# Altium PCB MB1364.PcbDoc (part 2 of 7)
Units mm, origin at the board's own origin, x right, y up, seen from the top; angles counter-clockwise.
Board outline 70 x 133.34 mm, 6 copper layers (Top Layer, Signal Layer 1, Signal Layer 2, Signal Layer 3, Signal Layer 4, Bottom Layer), stack 1.57 mm thick; 320 components, 286 nets, 1370 pads, 2009 vias.

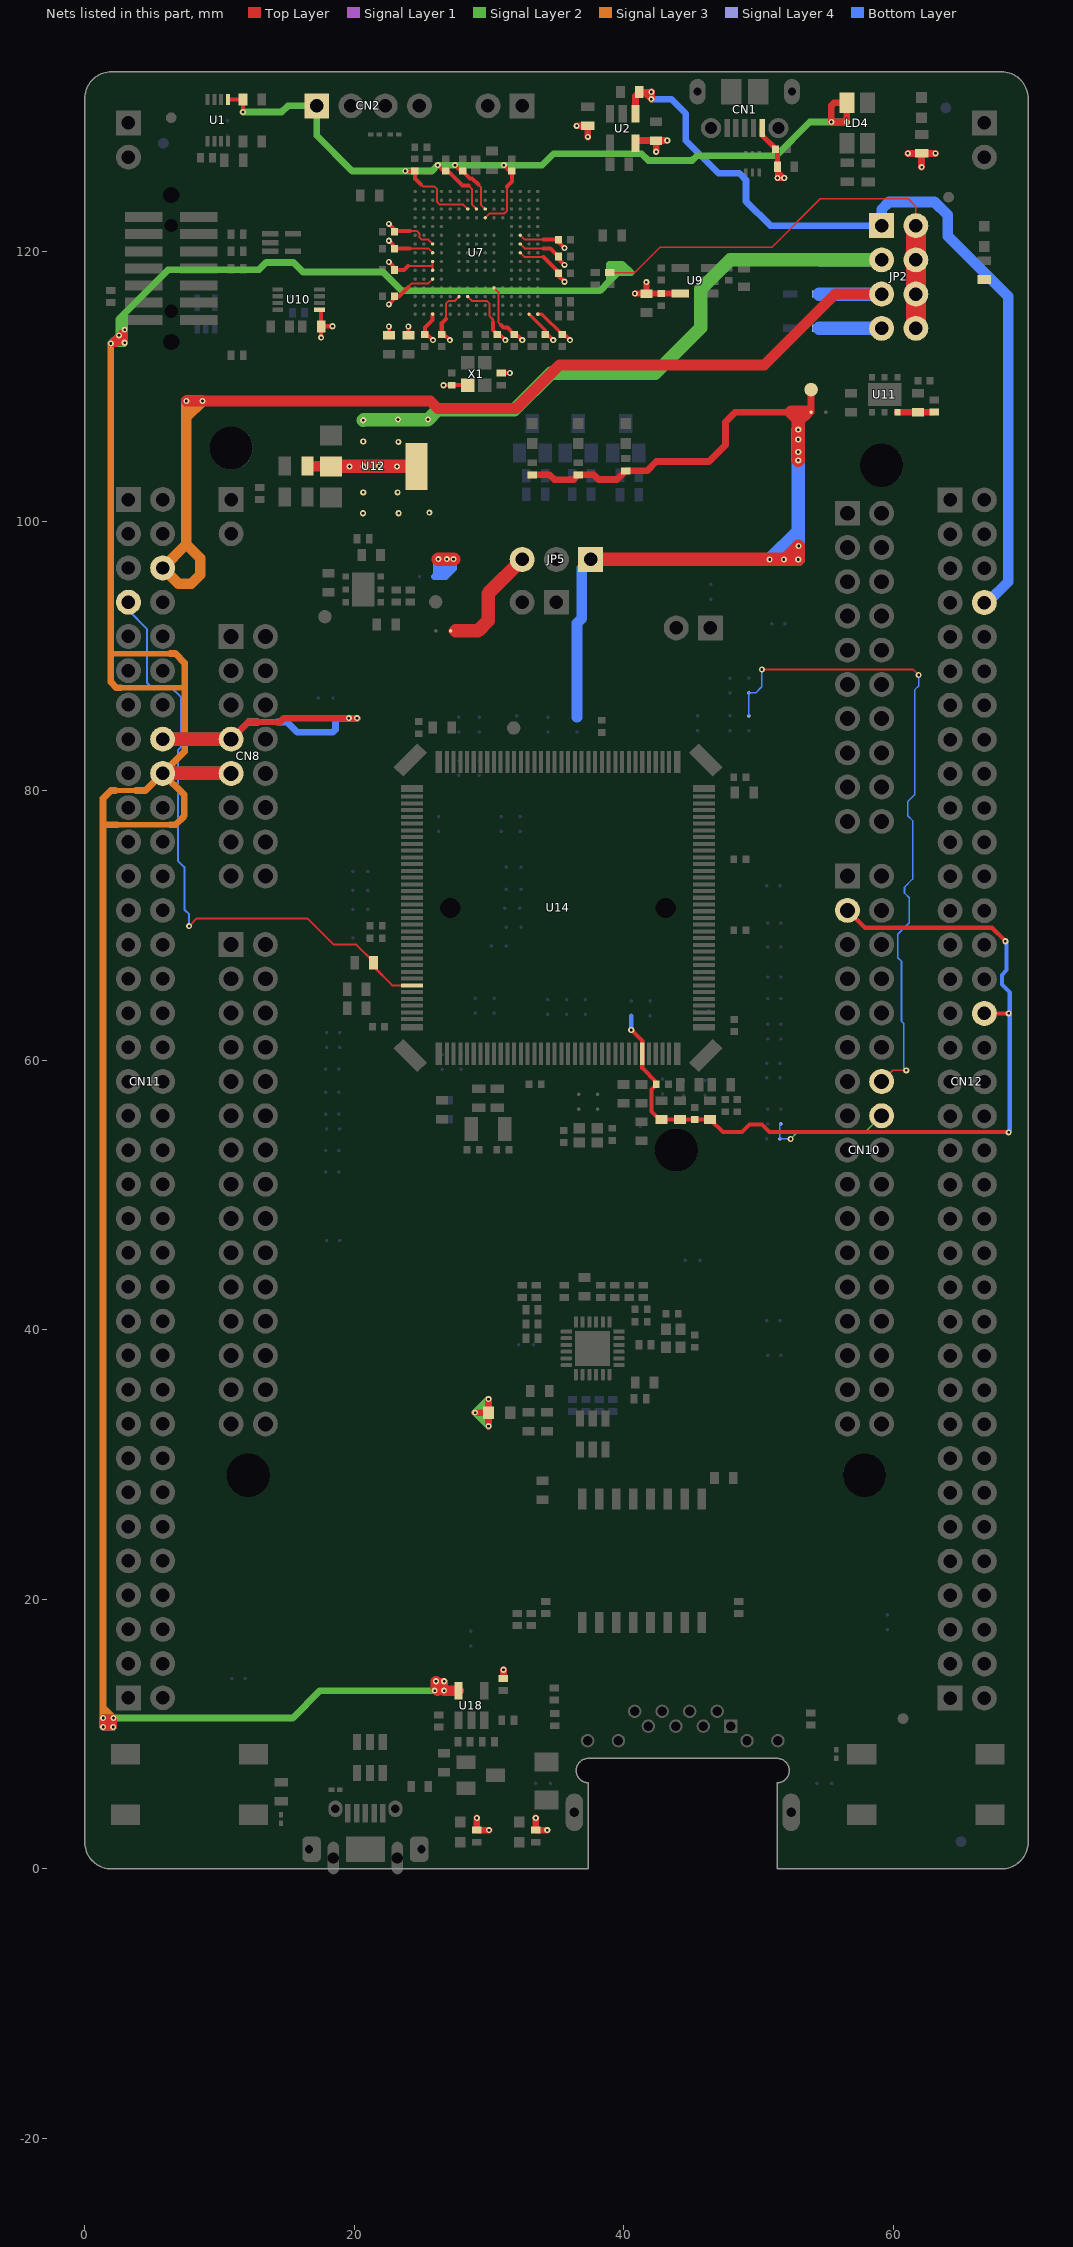
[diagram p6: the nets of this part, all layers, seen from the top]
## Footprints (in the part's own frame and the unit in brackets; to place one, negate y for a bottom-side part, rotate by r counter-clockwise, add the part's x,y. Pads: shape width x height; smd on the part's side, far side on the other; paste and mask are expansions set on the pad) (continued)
ICC_UFBGA201_176+25_10X10_P065 [mm] "IPC"
  round 0.25 smd mask+0.05: A1(-4.55,4.55) A2(-3.9,4.55) A3(-3.25,4.55) A4(-2.6,4.55) A5(-1.95,4.55) A6(-1.3,4.55) A7(-0.65,4.55) A8(0,4.55) A9(0.65,4.55) A10(1.3,4.55) A11(1.95,4.55) A12(2.6,4.55) A13(3.25,4.55) A14(3.9,4.55) A15(4.55,4.55) B1(-4.55,3.9) B2(-3.9,3.9) B3(-3.25,3.9) B4(-2.6,3.9) B5(-1.95,3.9) B6(-1.3,3.9) B7(-0.65,3.9) B8(0,3.9) B9(0.65,3.9) B10(1.3,3.9) B11(1.95,3.9) B12(2.6,3.9) B13(3.25,3.9) B14(3.9,3.9) B15(4.55,3.9) C1(-4.55,3.25) C2(-3.9,3.25) C3(-3.25,3.25) C4(-2.6,3.25) C5(-1.95,3.25) C6(-1.3,3.25) C7(-0.65,3.25) C8(0,3.25) C9(0.65,3.25) C10(1.3,3.25) C11(1.95,3.25) C12(2.6,3.25) C13(3.25,3.25) C14(3.9,3.25) C15(4.55,3.25) D1(-4.55,2.6) D2(-3.9,2.6) D3(-3.25,2.6) D4(-2.6,2.6) D5(-1.95,2.6) D6(-1.3,2.6) D7(-0.65,2.6) D8(0,2.6) D9(0.65,2.6) D10(1.3,2.6) D11(1.95,2.6) D12(2.6,2.6) D13(3.25,2.6) D14(3.9,2.6) D15(4.55,2.6) E1(-4.55,1.95) E2(-3.9,1.95) E3(-3.25,1.95) E4(-2.6,1.95) E12(2.6,1.95) E13(3.25,1.95) E14(3.9,1.95) E15(4.55,1.95) F1(-4.55,1.3) F2(-3.9,1.3) F3(-3.25,1.3) F4(-2.6,1.3) F6(-1.3,1.3) F7(-0.65,1.3) F8(0,1.3) F9(0.65,1.3) F10(1.3,1.3) F12(2.6,1.3) F13(3.25,1.3) F14(3.9,1.3) F15(4.55,1.3) G1(-4.55,0.65) G2(-3.9,0.65) G3(-3.25,0.65) G4(-2.6,0.65) G6(-1.3,0.65) G7(-0.65,0.65) G8(0,0.65) G9(0.65,0.65) G10(1.3,0.65) G12(2.6,0.65) G13(3.25,0.65) G14(3.9,0.65) G15(4.55,0.65) H1(-4.55,0) H2(-3.9,0) H3(-3.25,0) H4(-2.6,0) H6(-1.3,0) H7(-0.65,0) H8(0,0) H9(0.65,0) H10(1.3,0) H12(2.6,0) H13(3.25,0) H14(3.9,0) H15(4.55,0) J1(-4.55,-0.65) J2(-3.9,-0.65) J3(-3.25,-0.65) J4(-2.6,-0.65) J6(-1.3,-0.65) J7(-0.65,-0.65) J8(0,-0.65) J9(0.65,-0.65) J10(1.3,-0.65) J12(2.6,-0.65) J13(3.25,-0.65) J14(3.9,-0.65) J15(4.55,-0.65) K1(-4.55,-1.3) K2(-3.9,-1.3) K3(-3.25,-1.3) K4(-2.6,-1.3) K6(-1.3,-1.3) K7(-0.65,-1.3) K8(0,-1.3) K9(0.65,-1.3) K10(1.3,-1.3) K12(2.6,-1.3) K13(3.25,-1.3) K14(3.9,-1.3) K15(4.55,-1.3) L1(-4.55,-1.95) L2(-3.9,-1.95) L3(-3.25,-1.95) L4(-2.6,-1.95) L12(2.6,-1.95) L13(3.25,-1.95) L14(3.9,-1.95) L15(4.55,-1.95) M1(-4.55,-2.6) M2(-3.9,-2.6) M3(-3.25,-2.6) M4(-2.6,-2.6) M5(-1.95,-2.6) M6(-1.3,-2.6) M7(-0.65,-2.6) M8(0,-2.6) M9(0.65,-2.6) M10(1.3,-2.6) M11(1.95,-2.6) M12(2.6,-2.6) M13(3.25,-2.6) M14(3.9,-2.6) M15(4.55,-2.6) N1(-4.55,-3.25) N2(-3.9,-3.25) N3(-3.25,-3.25) N4(-2.6,-3.25) N5(-1.95,-3.25) N6(-1.3,-3.25) N7(-0.65,-3.25) N8(0,-3.25) N9(0.65,-3.25) N10(1.3,-3.25) N11(1.95,-3.25) N12(2.6,-3.25) N13(3.25,-3.25) N14(3.9,-3.25) N15(4.55,-3.25) P1(-4.55,-3.9) P2(-3.9,-3.9) P3(-3.25,-3.9) P4(-2.6,-3.9) P5(-1.95,-3.9) P6(-1.3,-3.9) P7(-0.65,-3.9) P8(0,-3.9) P9(0.65,-3.9) P10(1.3,-3.9) P11(1.95,-3.9) P12(2.6,-3.9) P13(3.25,-3.9) P14(3.9,-3.9) P15(4.55,-3.9) R1(-4.55,-4.55) R2(-3.9,-4.55) R3(-3.25,-4.55) R4(-2.6,-4.55) R5(-1.95,-4.55) R6(-1.3,-4.55) R7(-0.65,-4.55) R8(0,-4.55) R9(0.65,-4.55) R10(1.3,-4.55) R11(1.95,-4.55) R12(2.6,-4.55) R13(3.25,-4.55) R14(3.9,-4.55) R15(4.55,-4.55)
  silkscreen extent -5.22,-5.07 5.07,5.23, body extent -5.07,-5.07 5.07,5.07, height 0.61
ICC_VQFN24-EPAD_4X4_P050 [mm]
  rrect50% 0.85x0.3 smd mask+0.05: 1(-1.95,1.25) 2(-1.95,0.75) 3(-1.95,0.25) 4(-1.95,-0.25) 5(-1.95,-0.75) 6(-1.95,-1.25) 13(1.95,-1.25) 14(1.95,-0.75) 15(1.95,-0.25) 16(1.95,0.25) 17(1.95,0.75) 18(1.95,1.25)
  rrect50% 0.3x0.85 smd mask+0.05: 7(-1.25,-1.95) 8(-0.75,-1.95) 9(-0.25,-1.95) 10(0.25,-1.95) 11(0.75,-1.95) 12(1.25,-1.95) 19(1.25,1.95) 20(0.75,1.95) 21(0.25,1.95) 22(-0.25,1.95) 23(-0.75,1.95) 24(-1.25,1.95)
  rect 2.6x2.6 smd paste-10 mask+0.05: EP(0,0)
  silkscreen extent -2,-2 2,2, body extent -2.05,-2.05 2.05,2.05, height 1.1
ICC_VSSOP8_DCU_R-PDSO-G8_2X2P30_P050 [mm]
  rect 0.3x0.8 smd mask+0.05: 1(-0.75,-1.55) 2(-0.25,-1.55) 3(0.25,-1.55) 4(0.75,-1.55) 5(0.75,1.55) 6(0.25,1.55) 7(-0.25,1.55) 8(-0.75,1.55)
  silkscreen extent -1.05,-1.2 1.05,1.2, body extent -1.05,-1.62 1.05,1.62, height 0.9
L0603 [mm]
  rect 0.8x0.95 smd mask+0.05: 1(-0.8,0) 2(0.8,0)
  silkscreen extent -1.33,-0.6 1.33,0.6, body extent -0.87,-0.47 0.87,0.47, height 0.95
LED_0603_OSRAM_LG-Q396-PS-35_GREEN_1A2K_H0P4 [mm]
  rect 0.8x0.8 smd mask+0.05: 1(-0.75,0) 2(0.75,0)
  silkscreen extent -0.85,-0.53 1.28,0.53, body extent -0.85,-0.45 0.85,0.45, height 0.6
LED_0603_OSRAM_LS-Q976-NR-1_RED_1A2K_H0P8 [mm]
  rect 0.8x0.8 smd mask+0.05: 1(-0.75,0) 2(0.75,0)
  silkscreen extent -0.85,-0.53 1.28,0.53, body extent -0.85,-0.45 0.85,0.45, height 0.8
LED_0603_OSRAM_LY-Q396-P1Q2-36_YELLOW_1A2K_H0P4 [mm]
  rect 0.8x0.8 smd mask+0.05: 1(-0.75,0) 2(0.75,0)
  silkscreen extent -0.85,-0.53 1.28,0.53, body extent -0.85,-0.45 0.85,0.45, height 0.4
LED_0603_RED [mm]
  rect 0.8x0.8 smd mask+0.05: 1(-0.75,0) 2(0.75,0)
  silkscreen extent -0.25,-0.4 1.25,0.4, body extent -0.8,-0.4 0.8,0.4, height 0.6
LED_0603_VISHAY_VLMS1300-GS08_RED_1A2K_H0P8 [mm]
  rect 0.8x0.8 smd mask+0.05: 1(-0.75,0) 2(0.75,0)
  silkscreen extent -0.85,-0.53 1.28,0.53, body extent -0.85,-0.45 0.85,0.45, height 0.8
LED_BI-GR_HSMF-A201-A00J1 [mm] "MCD-00051"
  rect 1.1x1.5 smd mask+0.05: 1(-0.75,-1.5) 2(-0.75,1.5) 3(0.75,1.5) 4(0.75,-1.5)
  silkscreen extent -1.65,-1.85 1.5,1.7, body extent -1.5,-1.85 1.5,1.85, height 2.1
MIRE_PLACE_SMD_0P8MM [mm]
  round 0.8 smd paste-10 mask+0.2: 1(0,0)
  Top Layer keep-out circle w0.01: c0,0 r0.804
MOS_SOT23-5L [mm]
  rect 0.6x1.3 smd mask+0.05: 1(-0.95,-1.1) 2(0,-1.1) 3(0.95,-1.1) 4(0.95,1.1) 5(-0.95,1.1)
  silkscreen extent -1.6,-0.95 1.6,0.97, body extent -1.52,-1.25 1.52,1.25, height 1.45
NPN_SOT23 [mm]
  rect 1x1.4 smd mask+0.05: 1(-0.95,-1.1) 2(0.95,-1.1) 3(0,1.1)
  silkscreen extent -1.63,-0.82 1.63,0.82, body extent -1.56,-1.25 1.56,1.25, height 1.1
OSC_NDK_NZ2520SB_4P [mm]
  rect 1x1 smd mask+0.05: 1(-0.825,-0.625) 2(0.825,-0.625) 3(0.825,0.625) 4(-0.825,0.625)
  silkscreen extent -1.43,-1.22 1.2,1.05, body extent -1.3,-1.05 1.3,1.05, height 0.91
R0402 [mm]
  rect 0.51x0.7 smd mask+0.05: 1(-0.45,0) 2(0.45,0)
  silkscreen extent 0,-0.3 0,0.3, body extent -0.52,-0.3 0.52,0.3, height 0.4
R0603 [mm]
  rect 0.64x1 smd mask+0.05: 1(-0.7,0) 2(0.7,0)
  silkscreen extent -1.05,-0.58 1.05,0.58, body extent -0.9,-0.5 0.9,0.5, height 0.56
REG_SOT23-5L [mm]
  rect 0.6x1.3 smd mask+0.05: 1(-0.95,-1.1) 2(0,-1.1) 3(0.95,-1.1) 4(0.95,1.1) 5(-0.95,1.1)
  silkscreen extent -1.6,-0.95 1.6,0.97, body extent -1.52,-1.25 1.52,1.25, height 1.1
REG_SOT223-TAB [mm]
  rect 1.5x1.65 smd mask+0.05: 1(-2.3,-3.175) 2(0,-3.175) 3(2.3,-3.175)
  rect 3.5x1.65 smd mask+0.05: 4(0,3.175)
  silkscreen extent -3.35,-2.15 3.35,2.12, body extent -3.35,-3.48 3.35,3.48, height 1.8
Sheetbox_6L2S [mil] "Sheetbox 6 layers / 2 silkscreens"
  round 20 on Mech16: 1(813.5,208.05) 1(2736.63,208.05)
SOLDER-BRIDGE_R0402-0R [mil] "MCD-01619"
  round 10 smd paste-393.7: 1(-17.72,0) 2(20.67,0)
  Top Layer region: -30.51,-13.78 -30.51,13.78 -8.37,13.78 -1.48,0 -8.37,-13.78
  Top Layer region: 1.48,13.78 8.37,0 1.48,-13.78 30.51,-13.78 30.51,13.78
  silkscreen extent -33,-17 33,17, body extent -20,-12 20,12, height 14
SOLDER-BRIDGE_R0603-0R [mil]
  round 10 smd paste-393.7: 1(-19.68,0) 2(23.62,0)
  Top Layer region: -5.91,19.68 13.78,0 -5.91,-19.68 47.24,-19.68 47.24,19.68 -5.91,19.68
  Top Layer region: -47.24,-19.68 -47.24,19.68 -15.75,19.68 3.94,0 -15.75,-19.68 -47.24,-19.68
  silkscreen extent -50,-23 50,23, body extent -36,-20 36,20, height 22
SWI_WEALTHMETAL_TD-0341_4P_BLACK [mm]
  rect 1.52x2.16 smd mask+0.05: 1(-2.25,-4.75) 2(-2.25,4.75) 3(2.25,-4.75) 4(2.25,4.75)
  silkscreen extent -3,-3.5 3,3.5, body extent -3,-5.15 3,5.15, height 7.55
SWI_WEALTHMETAL_TD-0341_4P_BLUE [mm]
  rect 1.52x2.16 smd mask+0.05: 1(-2.25,-4.75) 2(-2.25,4.75) 3(2.25,-4.75) 4(2.25,4.75)
  silkscreen extent -3,-3.5 3,3.5, body extent -3,-5.15 3,5.15, height 7.55
TP_SMD_1MM [mm]
  round 1 smd paste-10 mask+0.05: 1(0,0)
  silkscreen extent -0.7,-0.7 0.7,0.7
TRS_DGKYD_KMS-1102NL [mm]
  rect 0.64x1.55 smd mask+0.05: 1(-4.445,-4.575) 2(-3.175,-4.575) 3(-1.905,-4.575) 4(-0.635,-4.575) 5(0.635,-4.575) 6(1.905,-4.575) 7(3.175,-4.575) 8(4.445,-4.575) 9(4.445,4.575) 10(3.175,4.575) 11(1.905,4.575) 12(0.635,4.575) 13(-0.635,4.575) 14(-1.905,4.575) 15(-3.175,4.575) 16(-4.445,4.575)
  silkscreen extent -6.35,-3.7 6.35,3.7, body extent -6.35,-4.7 6.35,4.7, height 6.3

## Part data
B1: library part MCD-00002, "Non-Open Push-Button 0.1A 24V", Manufacturer=WEALTHMETAL, Manufacturer_Part_Number=TD-0341
B2: library part MCD-00001, "Non-Open Push-Button 0.1A 24V BLACK", Manufacturer=WEALTHMETAL, Manufacturer_Part_Number=TD-0341
C1 C3 C18 C61 C64 C66: library part MCD-00238, "Capacitor, MLCC, 1uF, 6V3, X5R, 10%, 0603, T=0,8mm", Manufacturer=YAGEO, Manufacturer_Part_Number=CC0603KRX5R5BB105, Package=C0603
C2 C4 C26 C27 C44 C59 C65 C68 C73 C78 C79 C80 C82 C83: library part MCD-00237, "Capacitor, MLCC, 100nF, 6V3, X5R, 10%, 0603, T=0,8mm", Manufacturer=YAGEO, Manufacturer_Part_Number=CC0603KRX5R5BB104, Package=C0603
C5: library part MCD-00016, "Capacitor, MLCC, 20pF, 50V, NPO, 5%, 0402, T=0,5mm", Manufacturer=YAGEO, Manufacturer_Part_Number=CC0402JRNPO9BN200, Package=C0402
C6: library part MCD-00205, "Capacitor, MLCC, 100pF, 50V, NPO, 5%, 0402, T=0,5mm", Manufacturer=YAGEO, Manufacturer_Part_Number=CC0402JRNPO9BN101, Package=C0402
C7 C12 C13 C48 C50: library part MCD-00012, "Capacitor, MLCC, 2.2uF, 10V, X5R, 10%, 0603, T=0,8mm", Alternate_Manufacturer=KEMET, Alternate_Manufacturer_Part_Number=C0603C225K8PACTU, Manufacturer=YAGEO, Manufacturer_Part_Number=CC0603KRX5R6BB225, Package=C0603
C8 C9 C10 C11 C14 C15 C16 C17 C20 C21 C22 C24 C25 C28 C29 C30 C31 C32 C33 C34 C37: library part MCD-00102, "Capacitor, MLCC, 100nF, 16V, X7R, 10%, 0402, T=0,5mm", Alternate_Manufacturer=MURATA, Alternate_Manufacturer_Part_Number=GCM155R71C104KA55D, Manufacturer=YAGEO, Manufacturer_Part_Number=CC0402KRX7R7BB104, Package=C0402
C19: library part MCD-00011, "Capacitor, MLCC, 10nF, 16V, X7R, 10%, 0402, T=0.5mm", Manufacturer=YAGEO, Manufacturer_Part_Number=CC0402KRX7R7BB103, Package=C0402
C23 C36: library part MCD-00010, "Capacitor, MLCC, 1uF, 16V, X5R, 10%, 0603, T=0,8mm", Manufacturer=YAGEO, Manufacturer_Part_Number=CC0603KRX5R7BB105, Package=C0603
C35 C84: library part MCD-00009, "Capacitor, MLCC, 4.7uF, 16V, X5R, 10%, 0603, T=0.8mm", Manufacturer=YAGEO, Manufacturer_Part_Number=CC0603KRX5R7BB475, Package=C0603
C38 C62 C63: library part MCD-00006, "Capacitor, MLCC, 100nF, 16V, X7R, 10%, 0402, T=0.5mm", Alternate_Manufacturer=MURATA, Alternate_Manufacturer_Part_Number=GCM155R71C104KA55D, Manufacturer=YAGEO, Manufacturer_Part_Number=CC0402KRX7R7BB104, Package=C0402
C39 C45 C60: library part MCD-01121, "Capacitor, MLCC, 4.7µF, 10V, X5R, 20%, 0603, T=0,8mm", Manufacturer=MURATA, Manufacturer_Part_Number=GRM188R61A475ME15, Package=C0603
C40 C43: library part MCD-00097, "Capacitor, MLCC, 4.7uF, 16V, X5R, 20%, 0603, T=0,8mm", Alternate_Manufacturer=Murata, Alternate_Manufacturer_Part_Number=GRM188R61C475MAAJ, Manufacturer=MURATA, Manufacturer_Part_Number=GRM188R61C475KE11, Package=C0603
C41 C42: library part MCD-00014, "Capacitor, MLCC, 10uF, 25V, X5R, 10%, 0805, T=0,85mm", Manufacturer=YAGEO, Manufacturer_Part_Number=CC0805KRX5R8BB106, Package=C0805
C46 C47 C49 C51 C52 C53 C54 C55 C56 C57 C58 C67: library part MCD-01123, "[obsolete] Capacitor, MLCC,100nF, 10V, X7R, 10%, 0402, T=0.5mm", Manufacturer=MURATA, Manufacturer_Part_Number=NRND_GRM155R71A104KA01, Package=C0402
C69 C70 C75 C77: library part MCD-01374, "Capacitor, MLCC, 5.6pF, 50V, NPO, 5%, 0402, T=0,5mm", Manufacturer=YAGEO, Manufacturer_Part_Number=CC0402BRNPO9BN5R6, Package=C0402
C71 C72: library part MCD-00003, "Capacitor, MLCC, 5.1pF, 50V, NPO, +-0.25pF, 0402, T=0.5mm", Manufacturer=YAGEO, Manufacturer_Part_Number=CC0402CRNPO9BN5R1, Package=C0402
C74: library part MCD-00095, "Capacitor, MLCC, 1uF, 6V3, X5R, 10%, 0402, T=0,5mm", Alternate_Manufacturer=MURATA, Alternate_Manufacturer_Part_Number=GRM155R60J105KE19, Manufacturer_Part_Number=GRM155R61E105KA12, Package=C0402
C76: library part MCD-00724, "Capacitor, MLCC, 470pF, 50V, NPO, 5%, 0402, T=0,5mm", Manufacturer=YAGEO, Manufacturer_Part_Number=CC0402JRNPO9BN471, Package=C0402
C81: library part MCD-01124, "Capacitor, MLCC, 10µF, 10V, X5R, 10%, 0603, T=0.8mm", Manufacturer=MURATA, Manufacturer_Part_Number=GRM188R61A106KAAL, Package=C0603
C85: library part MCD-00722, "Capacitor, MLCC, 1nF, 2KV, X7R, 10%, 1206, T=1,25mm", Manufacturer=YAGEO, Manufacturer_Part_Number=CC1206KKX7RDBB102, Package=C1206
CN1: library part MCD-00028, "USB-MICRO-B, 0.65mm, RA, SMT, Bottom Mount,", Manufacturer=MOLEX, Manufacturer_Part_Number=1050170001
CN2: library part MCD-00029, "Header, 4x1, 2,54mm, VR, TH, Height 5.84mm/2.54mm", Manufacturer=SAMTEC, Manufacturer_Part_Number=TSW-104-07-x-S
CN3 CN4 CN15 CN16: library part MCD-00214, "Header, 2x1, 2,54mm, VR, TH, Height 5.84mm/10.16mm", Manufacturer=SAMTEC, Manufacturer_Part_Number=TSW-102-09-x-S
CN5: library part MCD-01226, "Header 5x2, 1.27mm, Dual row, Straight, Surface mount, vertical male connector. 3.05mm lead. Mates with FFSD connector. Footprint compatible with FTSH-107-01-L-DV,-K,-A,-P,-ES (STDC14 MEDIUM)", Alternate_Manufacturer=JIUBABA, Alternate_Manufacturer_Part_Number=P127B-2x05MGF-079-1A, Manufacturer=SAMTEC, Manufacturer_Part_Number=FTSH-105-01-L-DV-K
CN7: library part MCD-01039, "Socket, 10x2, 2.54mm, VR, TH, Height 8.51mm/10mm, Low insertion force.", Manufacturer=SAMTEC, Manufacturer_Part_Number=SSW-110-23-x-D
CN8: library part MCD-01037, "Socket, 8x2, 2.54mm, VR, TH, Height 8.51mm/10mm, Low insertion force.", Manufacturer=SAMTEC, Manufacturer_Part_Number=SSW-108-23-x-D
CN9: library part MCD-01040, "Socket, 15x2, 2.54mm, VR, TH, Height 8.51mm/10mm, Low insertion force.", Manufacturer=SAMTEC, Manufacturer_Part_Number=SSW-115-23-x-D
CN10: library part MCD-01041, "Socket, 17x2, 2.54mm, VR, TH, Height 8.51mm/10mm, Low insertion force", Manufacturer=SAMTEC, Manufacturer_Part_Number=SSW-117-23-x-D
CN11 CN12: library part MCD-01210, "Header, 35x2, 2,54mm, VR, TH, Height 5.84mm/2.54mm", Manufacturer=SAMTEC, Manufacturer_Part_Number=TSW-135-07-x-D
CN13: library part MCD-00661, "USB-MICRO-AB Receptacle, RA, SMT + DIP, Standard, Top Mount, USB certified (symbol & footprint compatible with MCD-00022)", Manufacturer=HIROSE, Manufacturer_Part_Number=ZX62RD-AB-5P8(30)
CN14: library part MCD-00717, "RJ45 jack, single port, with LEDS, Metal shielded dip low profile", Manufacturer="DONGGUAN KEYOUDA ELECTRONIC TECHNOLOGY", Manufacturer_Part_Number=KRJ-CB4.2GYZNL
D1 D2 D3: library part MCD-00034, Manufacturer=STMICROELECTRONICS
JP1: library part MCD-00045, "Header, 2x1, 2,54mm, VR, TH, Height 5.84mm/2.54mm", Alternate_Manufacturer="JIUBABA; LIANYI", Alternate_Manufacturer_Part_Number=313102S111116;313102S111116, Manufacturer=SAMTEC, Manufacturer_Part_Number=TSW-102-07-x-S
JP2: library part MCD-00686, "Header, 4x2, 2,54mm, VR, TH, Height 5.84mm/2.54mm - Shunt Fitted 1-2", Manufacturer=SAMTEC, Manufacturer_Part_Number=TSW-104-07-x-D
JP3 JP4 JP6: library part MCD-00683, "Header, 2x1, 2,54mm, VR, TH, Height 5.84mm/2.54mm - Shunt Fitted by default", Alternate_Manufacturer=LIANYI, Alternate_Manufacturer_Part_Number=313102S111116, Manufacturer=SAMTEC, Manufacturer_Part_Number=TSW-102-07-x-S
JP5: library part MCD-00684, "Header, 3x1, 2,54mm, VR, TH, Height 5.84mm/2.54mm - Shunt Fitted 1-2 by default", Manufacturer=SAMTEC, Manufacturer_Part_Number=TSW-103-07-F-S
L1: library part MCD-00047, "SMD Chip ferrite bead, 600R@100MHz +/-25%, 350mA, 500mohm DC, 0603, T=0.8mm", Manufacturer=TAI-TECH, Manufacturer_Part_Number=FCM1608KF-601T03
LD1 LD5 LD8: library part MCD-00588, "LED Green, 0603 SMD, Forward Voltage Typ=2V, Max=2.5V", Alternate_Manufacturer="VISHAY SEMICONDUCTOR OPTO DIVISION", Alternate_Manufacturer_Part_Number=VLMTG1300-GS08, Manufacturer="OSRAM OPTO SEMICONDUCTORS", Manufacturer_Part_Number="LG Q396-PS-35", Package="LED 0603"
LD2: library part MCD-01061, "LED Yellow, 0603 SMD, Forward Voltage min=1.7V, Typ=2V, Max=2.3V", Manufacturer="OSRAM OPTO SEMICONDUCTORS", Manufacturer_Part_Number="LY Q396-P1Q2-36"
LD3: library part MCD-00586, "LED Red, 0603 SMD, Forward Voltage Typ=2V, Max=2.5V", Alternate_Manufacturer="VISHAY SEMICONDUCTOR OPTO DIVISION", Alternate_Manufacturer_Part_Number=VLMS1300-GS08, Manufacturer="OSRAM OPTO SEMICONDUCTORS", Manufacturer_Part_Number="LS Q976-NR-1", Package="LED 0603"
LD4: library part MCD-00051, "LED Bicolor", Alternate_Manufacturer=EVERLUCK, Alternate_Manufacturer_Part_Number=LE-RGW35280, Manufacturer="AVAGO TECHNOLOGIES", Manufacturer_Part_Number=HSMF-A201-A00J1
LD6: library part MCD-00049, "LED, Red, 0603", Manufacturer=EVERLIGHT, Manufacturer_Part_Number=19-213-R6C-AP1Q2B/3T, Package="LED 0603"
LD7: library part MCD-00587, "LED Red, 0603 SMD, 2V Forward Voltage", Alternate_Manufacturer="OSRAM OPTO SEMICONDUCTORS", Alternate_Manufacturer_Part_Number="LS Q976-NR-1", Manufacturer=VISHAY, Manufacturer_Part_Number=VLMS1300-GS08, Package="LED 0603"
Q1 Q2 Q3 T1: library part MCD-00073, "NPN Bipolar Transistor", Alternate_Manufacturer="ON SEMICONDUCTOR", Alternate_Manufacturer_Part_Number="MMBT2222ALT1G / MMBT2222ALT3G", Manufacturer_Part_Number=BSR14
R1 R4 R64 R68 R69 R70: library part MCD-00223, "Resistor,100K,0603,1%,1/10W", Manufacturer=YAGEO, Manufacturer_Part_Number=RC0603FR-07100KL, Package=R0603
R2: library part MCD-00070, "Resistor,1K,0603,1%,1/10W", Manufacturer=YAGEO, Manufacturer_Part_Number=RC0603FR-071KL, Package=R0603
R3 R10 R11 R13 R23 R29: library part MCD-00189, "Resistor,22R,0402,1%,1/16W", Manufacturer=YAGEO, Manufacturer_Part_Number=RC0402FR-0722RL, Package=R0402
R5 R17 R21 R67: library part MCD-00119, "Resistor,100R,0402,1%,1/16W", Manufacturer=YAGEO, Manufacturer_Part_Number=RC0402FR-07100RL, Package=R0402
R6: library part MCD-00185, "Resistor,3K,0402,1%,1/16W", Manufacturer=YAGEO, Manufacturer_Part_Number=RC0402FR-073KL, Package=R0402
R7 R33 R34 R35: library part MCD-00220, "Resistor,10K,0603,1%,1/10W", Manufacturer=YAGEO, Manufacturer_Part_Number=RC0603FR-0710KL, Package=R0603
R8 R9 R74: library part MCD-00197, "Resistor,330R,0603,1%,1/10W", Manufacturer=YAGEO, Manufacturer_Part_Number=RC0603FR-07330RL, Package=R0603
R12: library part MCD-00500, "Resistor,620R,0603,1%,1/10W", Manufacturer=YAGEO, Manufacturer_Part_Number=RC0603FR-07620RL, Package=R0603
R14 R18 R20: library part MCD-00065, "Resistor,4K7,0402,1%,1/16W", Alternate_Manufacturer=YAGEO, Alternate_Manufacturer_Part_Number=RT0402FRE074K7L, Manufacturer_Part_Number=RC0402FR-074K7L, Package=R0402
R15: library part MCD-00055, "Resistor,2K7,0402,1%,1/16W", Manufacturer=YAGEO, Manufacturer_Part_Number=RC0402FR-072K7L, Package=R0402
R22 R24 R25 R30 R40 R42 R43 R46 R48 R57 R60 R63: library part MCD-00053, "Resistor,10K,0402,1%,1/16W", Manufacturer=YAGEO, Manufacturer_Part_Number=RC0402FR-0710KL, Package=R0402
R26 R27 R58 R59 R66: library part MCD-00441, "Resistor,270R,0402,1%,1/16W", Manufacturer=YAGEO, Manufacturer_Part_Number=RC0402FR-07270RL, Package=R0402
R28: library part MCD-00178, "Resistor,470R,0402,1%,1/16W", Manufacturer=YAGEO, Manufacturer_Part_Number=RC0402FR-07470RL, Package=R0402
R31: library part MCD-00443, "Resistor,27K,0402,1%,1/16W", Manufacturer=YAGEO, Manufacturer_Part_Number=RC0402FR-0727KL, Package=R0402
R32: library part MCD-00493, "Resistor,56K,0402,1%,1/16W", Manufacturer=YAGEO, Manufacturer_Part_Number=RC0402FR-0756KL, Package=R0402
R36 R37 R38 R39: library part MCD-00056, "Resistor,0R,0603,5%,1/10W", Manufacturer=YAGEO, Manufacturer_Part_Number=RC0603JR-070RL, Package=R0603
R41 R44 R45 R49: library part MCD-00455, "Resistor,33R,0402,1%,1/16W", Manufacturer=YAGEO, Manufacturer_Part_Number=RC0402FR-0733RL, Package=R0402
R47: library part MCD-00068, "Resistor,1K5,0402,1%,1/16W", Manufacturer=YAGEO, Manufacturer_Part_Number=RC0402FR-071K5L, Package=R0402
R50: library part MCD-00052, "Resistor,0R,0402,5%,1/16W", Manufacturer=YAGEO, Manufacturer_Part_Number=RC0402JR-070RL, Package=R0402
R51: library part MCD-00723, "Resistor,12K1,0402,1%,1/16W", Manufacturer=YAGEO, Manufacturer_Part_Number=RC0402FR-0712K1L, Package=R0402
R52 R53 R54 R55: library part MCD-00515, "Resistor,75R,0402,1%,1/16W", Manufacturer=YAGEO, Manufacturer_Part_Number=RC0402FR-0775RL, Package=R0402
R56 R61 R62: library part MCD-00063, "Resistor,47K,0402,1%,1/16W", Manufacturer=YAGEO, Manufacturer_Part_Number=RC0402FR-0747KL, Package=R0402
R65: library part MCD-00461, "Resistor,360R,0402,1%,1/16W", Manufacturer=YAGEO, Manufacturer_Part_Number=RC0402FR-07360RL, Package=R0402
R71 R72 R73: library part MCD-00222, "Resistor,47K,0603,1%,1/10W", Manufacturer=YAGEO, Manufacturer_Part_Number=RC0603FR-0747KL, Package=R0603
R75 R76 R77 R78: library part MCD-00565, "Resistor,49R9,0402,1%,1/16W", Manufacturer=YAGEO, Manufacturer_Part_Number=RC0402FR-0749R9L, Package=R0402
SB1 SB2 SB3 SB4 SB5 SB6 SB7 SB8 SB9 SB11 SB12 SB13 SB14 SB15 SB16 SB17 SB18 SB19 SB20 SB21 SB22 SB23 SB24 SB25 SB26 SB27 SB29 SB30 SB31 SB32 SB33 SB34 SB35 SB36 SB39 SB40 SB41 SB42 SB43 SB44 SB45 SB46 SB47 SB51 SB52 SB56 SB57 SB58 SB64 SB72 SB74 SB76 SB77 SB78 SB79 SB80: library part MCD-00071, "Solder Bridge ON", Manufacturer=YAGEO, Manufacturer_Part_Number=RC0603JR-070RL, Package=SB0603
SB28 SB37 SB38 SB48 SB49 SB50 SB53 SB54 SB55 SB59 SB60 SB61 SB62 SB63 SB65 SB66 SB67 SB68 SB69 SB70 SB71 SB73 SB75 SB81 SB82: library part MCD-01618, "Solder Bridge 0402 ON", Manufacturer=YAGEO, Manufacturer_Part_Number=RC0402JR-070RL, Package=SB0402
TP1 TP2 TP3 TP4: library part MCD-00074, "Test Point 1mm", Manufacturer=n/a
U1 U10: library part MCD-00264, "Dual bit dual supply bus transceiver", Manufacturer="TEXAS INSTRUMENTS"
U2: library part MCD-00159, "500mA, Enhanced single channel power switches with active high enable pin", Alternate_Manufacturer="TEXAS INSTRUMENTS", Alternate_Manufacturer_Part_Number=TPS2051C, Manufacturer=STMICROELECTRONICS
U3 U4 U20 U22 U23: library part MCD-00170, "ESD protection 6V1", Manufacturer=STMICROELECTRONICS, Manufacturer_Part_Number=ESDALC6V1-1U2
U5: library part MCD-00649, "Common mode filter with ESD protection for USB 2.0 interface", Manufacturer=STMICROELECTRONICS
U6 U21: library part MCD-00251, "High power transient voltage suppressor, 7V breakdown", Manufacturer=STMICROELECTRONICS, Manufacturer_Part_Number=ESDA7P60-1U1M
U7: library part MCD-00596, "STM32F723IEK  (STM32F7) BGA176", Manufacturer=STMICROELECTRONICS, Manufacturer_Part_Number=STM32F723IEK6
U8 U24: library part MCD-00136, "Dual Transil array for ESD protection", Manufacturer=STMICROELECTRONICS
U9: library part MCD-00086, "Ultra low drop-low noise BiCMOS voltage, regulators low ESR capacitors compatible", Manufacturer=STMICROELECTRONICS
U11: library part MCD-01025, "LDO, 3.3V, 1.3A, Very low quiescent current BiCMOS voltage regulator", Manufacturer=STMICROELECTRONICS, Package=DFN6-3x3
U12: library part MCD-00088, "IC REG LDO 5V 0.8A SOT223", Manufacturer=STMICROELECTRONICS, Package=SOT-223
U13: library part MCD-00581, "LDO Linear Voltage Regulator IC Positive Adjustable 1 Output Adjustable 1.3A 6-DFN (3x3)", Manufacturer=STMICROELECTRONICS, Package="DFN6 (3x3)"
U14: library part MCD-01349, "STM32H7A3ZIT6U, LQFP144 package, 20x20", Manufacturer=STMICROELECTRONICS, Manufacturer_Part_Number=STM32H7A3ZIT6U, Package=LQFP144
U15: library part MCD-00719, "10/100M RMII Ethernet transceiver", Manufacturer=MICROCHIP
U16: library part MCD-00250, "Very low capacitance ESD protection , 4 lines", Manufacturer=STMICROELECTRONICS
U17: library part MCD-00718, "Discrete Magnetic Transformer Module, 16 pins, SMT, 100 Base-TX", Manufacturer="DONGGUAN KEYOUDA ELECTRONIC TECHNOLOGY"
U18: library part MCD-00083, "Enhanced single channel power switches with active low enable pin", Alternate_Manufacturer="TEXAS INSTRUMENTS", Alternate_Manufacturer_Part_Number=TPS2041C, Manufacturer=STMICROELECTRONICS
U19: library part MCD-00163, "Very low capacitance ESD protection", Manufacturer=STMICROELECTRONICS
X1: library part MCD-00597, "Oscillator 25Mhz, +-50ppm, Vcc:3.3V typ, square wave: [0.1Vcc;0.9Vcc], Enable pin, SMD", Alternate_Manufacturer=NDK, Alternate_Manufacturer_Part_Number="NZ2520SB 25MHz END4869B", Manufacturer_Part_Number="NZ2520SH 25MHz END4869C"
X2: library part MCD-00091, "Crystal 32.768kHz, 6pF, +-20ppm, 50Kohms max, SMD", Manufacturer=NDK, Manufacturer_Part_Number="NX3215SA 32.768KHz EXS00A-MU00525"
X3 X4: library part MCD-01364, "Crystal 25MHz, 6pF, +-20ppm, 80ohms max, SMD", Manufacturer=NDK, Manufacturer_Part_Number="NX2016SA 25MHz EXS00A-CS11321", Package=NX2016SA

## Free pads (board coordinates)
  round 3.2 hole 3.2 unplated: 0(10.866,105.409) 0(12.136,29.209) 0(43.886,53.339) 0(57.856,29.209) 0(59.126,104.139)

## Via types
v1: diameter 0.45, hole 0.2, Top Layer to Bottom Layer, tented both sides, 1933 vias
v2: diameter 0.45, hole 0.2, Top Layer to Bottom Layer, tented top, 67 vias
v3: diameter 0.6, hole 0.3, Top Layer to Bottom Layer, tented both sides, 9 vias

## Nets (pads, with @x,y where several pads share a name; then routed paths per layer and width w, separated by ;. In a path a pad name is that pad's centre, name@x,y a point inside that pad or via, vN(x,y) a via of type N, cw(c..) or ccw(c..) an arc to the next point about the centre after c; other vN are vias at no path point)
1V8: JP5.3 SB80.2 | length 8.5
  Top Layer w0.6: 27.3,91.85 27.525,91.85
  Top Layer w1: 27.525,91.85 29.175,91.85 29.925,92.6 29.925,94.623 JP5.3@32.456,97.154
3V3: CN8.7 CN11.16 JP5.1 L1.2 R26.2 R27.2 R28.2 R56.1 R65.2 R66.2 SB2.2 SB6.1 SB13.1 SB20.1 TP1.1 | length 155.2
  Top Layer w0.4: 12.845,85.089 14.501,85.089
  Top Layer w0.5: CN8.7@10.866,83.819 12.136,85.089 12.845,85.089 ; 14.501,85.089 14.791,85.379 19.166,85.379 v1@20.2,85.379 ; v1(28.966,33.854) L1.2@29.966,33.854 ; v1(29.091,3.779) R65.2@29.091,2.879 v1(29.991,2.879) ; v1(29.966,32.854) L1.2@29.966,33.854 ; v1(29.966,34.854) L1.2@29.966,33.854 ; R56.1@31.066,14.129 v1(31.066,14.779) ; R27.2@33.216,103.429 34.487,103.429 34.841,103.075 36.262,103.075 R28.2@36.616,103.429 37.771,103.429 38.121,103.079 39.491,103.079 R26.2@40.141,103.729 41.711,103.729 42.407,104.425 46.325,104.425 47.55,105.65 47.55,107.35 48.279,108.079 52.425,108.079 ; v1(33.466,3.779) R66.2@33.466,2.879 v1(34.316,2.879) ; 53.55,108.079 SB2.2@53.891,108.079 TP1.1@53.891,109.754
  Top Layer w1: CN11.16@5.786,83.819 CN8.7@10.866,83.819 ; v1(26.241,97.179) v1(26.866,97.179) v1(27.366,97.179) ; JP5.1@37.536,97.154 v1(50.816,97.154) v1(51.866,97.154) v1@51.966,97.154 ; v1(52.941,104.504) v1(52.941,105.129) v1(52.941,106.054) v1(52.941,106.779) 52.941,107.47 ; v1@51.966,97.154 52.941,98.129 v1(52.941,97.154) v1@51.966,97.154 ; 52.941,107.47 52.941,107.563 52.425,108.079 53.55,108.079 52.941,107.47
  Signal Layer 2 w0.5: v1(19.6,85.375) v1(20.2,85.375) ; v1(26.241,97.179) v1(26.866,97.179) v1(27.366,97.179) ; v1(28.966,33.854) 29.676,33.854 ; v1(28.966,33.854) 29.676,33.144 ; v1(28.966,33.854) 29.676,34.564 ; 29.676,33.144 29.676,33.854 ; 29.676,33.144 v1(29.966,32.854) v1(29.966,34.854) 29.676,34.564 ; 29.676,33.854 29.676,34.564
  Signal Layer 2 w0.6: v1(50.816,97.154) v1(51.866,97.154) v1@51.966,97.154 ; v1(52.941,104.504) v1(52.941,105.129) v1(52.941,106.054) v1(52.941,106.779) ; v1@51.966,97.154 v1(52.966,98.154) 52.966,97.179 v1(52.941,97.154) v1@51.966,97.154
  Signal Layer 2 w1: CN11.16@5.786,83.819 CN8.7@10.866,83.819
  Signal Layer 3 w0.5: v1(19.6,85.375) v1(20.2,85.375) ; v1(26.241,97.179) v1(26.866,97.179) v1(27.366,97.179)
  Signal Layer 3 w0.6: v1@50.941,97.154 v1(51.866,97.154) v1@51.966,97.154 ; v1(52.941,104.504) v1(52.941,105.129) v1(52.941,106.054) v1(52.941,106.779) ; v1@51.966,97.154 v1(52.966,98.154) 52.966,97.179 v1(52.941,97.154) v1@51.966,97.154
  Bottom Layer w0.4: 12.845,85.089 14.281,85.089
  Bottom Layer w0.5: CN8.7@10.866,83.819 12.136,85.089 12.845,85.089 ; 14.281,85.089 15.011,85.089 15.775,84.325 18.4,84.325 18.6,84.525 18.6,85.2 SB20.1@18.425,85.375 v1(19.6,85.375) v1(20.2,85.375) ; 26.1,96.379 26.866,97.145 v1(26.866,97.179) ; 26.1,96.379 26.1,97.038 v1(26.241,97.179) v1(26.866,97.179) ; 26.1,96.379 26.1,96.038 SB6.1@25.941,95.879 26.254,95.879 ; 26.254,95.879 26.779,95.879 27.366,96.466 v1@27.366,96.991 ; 26.254,95.879 v1@27.366,96.991 ; v1(26.866,97.179) v1(27.366,97.179) v1@27.366,96.991 ; v1(28.966,33.854) 29.62,33.199 ; v1(28.966,33.854) 29.62,33.854 ; v1(28.966,33.854) 29.62,34.508 ; 29.62,33.199 v1(29.966,32.854) 29.966,33.925 ; 29.62,33.199 29.62,33.854 ; 29.62,33.854 29.895,33.854 29.966,33.925 ; 29.62,33.854 29.62,34.508 ; 29.62,34.508 v1(29.966,34.854) 29.966,33.925
  Bottom Layer w0.8: SB13.1@36.525,85.45 36.525,92.425 36.875,92.775 36.875,96.493 JP5.1@37.536,97.154
  Bottom Layer w1: v1(50.816,97.154) v1@50.841,97.154 ; v1(52.941,106.779) v1(52.941,106.054) v1(52.941,105.129) v1(52.941,104.504) 52.941,99.254 ; v1@50.841,97.154 52.941,99.254 ; v1@50.841,97.154 v1(51.866,97.154) ; v1(51.866,97.154) v1@52.941,98.229 ; v1(51.866,97.154) v1(52.941,97.154) v1@52.941,98.229 ; v1@52.941,98.229 52.941,99.254
3V3_STLK: C2.2 C8.2 C9.2 C10.2 C11.2 C14.2 C15.2 C16.2 C17.2 C21.2 C22.2 C23.2 C24.2 C25.2 C27.2 C29.2 C30.2 C31.2 C32.2 C33.2 C34.2 C35.2 C36.2 C37.2 CN2.1 LD4.4 R24.1 U1.1 U7.C1 U7.C5 U7.C6 U7.C7 U7.C8 U7.C9 U7.F3 U7.G3 U7.G13 U7.H13 U7.J12 U7.J13 U7.K4 U7.N8 U7.N9 U7.N10 U7.P1 U7.R1 U9.5 U10.1 X1.4 | length 141.5
  Top Layer w0.15: 23.996,118.924 25.224,118.924 ; 24.016,117.379 24.271,117.634 25.496,117.634 U7.C5@25.816,117.954 ; 24.116,120.229 25.491,120.229 U7.C8@25.816,119.904 ; 24.141,121.529 24.644,121.529 24.836,121.336 24.836,121.059 25.016,120.879 25.491,120.879 U7.C9@25.816,120.554 ; 24.966,124.954 25.091,124.829 25.941,124.829 26.146,124.624 26.146,123.671 26.339,123.479 28.091,123.479 U7.G13@28.416,123.154 ; 25.225,118.925 25.224,118.924 ; 25.8,118.95 25.774,118.924 25.224,118.924 ; U7.C6@25.816,118.604 U7.C7@25.816,119.254 ; 26.791,114.979 26.791,116.131 26.984,116.324 27.436,116.324 U7.F3@27.766,116.654 ; U7.G3@28.416,116.654 28.736,116.334 29.839,116.334 30.036,116.136 30.036,115.209 30.291,114.954 30.291,114.779 ; 28.466,124.904 28.746,124.624 28.746,123.474 U7.H13@29.066,123.154 ; 29.216,124.954 29.396,124.774 29.396,123.474 U7.J13@29.716,123.154 ; U7.J12@29.716,122.504 30.041,122.829 31.144,122.829 31.336,123.021 31.336,124.799 31.341,124.804 ; U7.K4@30.366,117.304 30.686,116.984 30.686,114.759 30.891,114.554 ; U7.N8@32.316,119.904 32.641,119.579 34.041,119.579 ; U7.N9@32.316,120.554 32.641,120.229 34.041,120.229 ; U7.N10@32.316,121.204 32.641,120.879 34.041,120.879
  Top Layer w0.25: U7.P1@32.966,115.354 34.166,114.154 C33.2@34.166,113.854 ; U7.R1@33.616,115.354 33.916,115.354 C34.2@35.416,113.854
  Top Layer w0.3: U1.1@10.616,131.279 C2.2@11.741,131.279 v1(11.741,130.354) ; U10.1@17.416,115.679 17.541,115.554 C27.2@17.541,114.454 ; v1(17.541,113.604) C27.2@17.541,114.454 ; v1(18.391,114.454) C27.2@17.541,114.454 ; v1(22.562,116.083) 22.991,116.512 C25.2@22.991,116.679 23.316,116.679 24.016,117.379 ; v1(22.562,119.225) 22.991,118.796 C21.2@22.991,118.629 23.701,118.629 23.996,118.924 ; v1(22.562,120.8) 22.991,120.371 C16.2@22.991,120.204 23.016,120.229 24.116,120.229 ; v1(22.562,122.05) 22.991,121.621 C14.2@22.991,121.454 23.066,121.529 24.141,121.529 ; C35.2@22.566,113.779 v1(22.566,114.429) ; v1(23.791,125.979) C8.2@24.491,125.979 24.491,125.429 24.966,124.954 ; C36.2@24.016,113.779 v1(24.016,114.429) ; U7.C1@25.816,115.354 25.816,114.929 25.241,114.354 C29.2@25.241,113.854 25.408,113.854 v1(25.837,113.425) ; v1(26.195,126.408) 26.624,125.979 C9.2@26.791,125.979 26.966,125.979 28.041,124.904 28.466,124.904 ; v1(26.616,110.079) C37.2@27.241,110.079 X1.4@28.416,110.079 ; 26.791,114.979 26.491,114.679 C30.2@26.491,113.854 26.658,113.854 v1(27.087,113.425) ; v1(27.47,126.408) 27.899,125.979 C10.2@28.041,125.979 ; C10.2@28.066,125.979 C10.2@28.041,125.979 ; 29.216,124.954 28.741,125.429 28.579,125.429 28.041,125.967 C10.2@28.041,125.979 ; 30.291,114.779 30.291,114.179 C31.2@30.616,113.854 30.783,113.854 v1(31.212,113.425) ; 30.891,114.554 31.086,114.359 31.361,114.359 C32.2@31.866,113.854 32.033,113.854 v1(32.462,113.425) ; R24.1@30.916,110.979 v1(31.541,110.979) ; v1(31.095,126.408) 31.524,125.979 C11.2@31.691,125.979 31.716,125.954 31.716,125.179 31.341,124.804 ; 34.041,119.579 35.141,118.479 C22.2@35.141,118.379 C22.2@35.166,118.354 ; 34.041,120.229 34.541,120.229 C17.2@35.141,119.629 C17.2@35.166,119.604 ; 34.041,120.879 C15.2@35.141,120.879 C15.2@35.166,120.854 ; C33.2@34.166,113.854 34.333,113.854 v1(34.762,113.425) ; C22.2@35.141,118.354 C22.2@35.166,118.354 ; C17.2@35.141,119.604 C17.2@35.166,119.604 ; C15.2@35.141,120.854 C15.2@35.166,120.854 ; C34.2@35.416,113.854 35.583,113.854 v1(36.012,113.425) ; v1(35.595,117.758) 35.166,118.187 C22.2@35.166,118.354 ; v1(35.595,119.008) 35.166,119.437 C17.2@35.166,119.604 ; v1(35.595,120.258) 35.166,120.687 C15.2@35.166,120.854
  Top Layer w0.45: v1(40.816,116.879) C23.2@41.666,116.879 ; v1(41.666,117.729) C23.2@41.666,116.879 ; U9.5@44.191,116.879 C24.2@42.791,116.879 C23.2@41.666,116.879
  Top Layer w0.5: v1(55.391,129.604) v1(56.541,129.604) 56.541,131.004 LD4.4@56.566,131.029 55.591,131.029 55.391,130.829 v1(55.391,129.604)
  Signal Layer 2 w0.5: v1(11.741,130.354) 14.616,130.354 15.071,130.809 CN2.1@17.216,130.809 17.216,128.604 19.846,125.974 25.761,125.974 v1(26.195,126.408) v1(27.47,126.408) v1(31.095,126.408) 33.945,126.408 34.791,127.254 41.316,127.254 41.816,126.754 45.066,126.754 45.411,127.099 51.286,127.099 53.791,129.604 v1(55.391,129.604) v1(56.541,129.604)
5V: C40.2 CN8.9 CN11.18 JP2.2 JP2.4 JP2.6 JP2.8 R12.2 R15.1 R25.2 U11.6 U18.5 | length 322
  Top Layer w0.12: R15.1@38.941,118.429 40.791,118.429 42.666,120.304 50.966,120.304 54.566,123.904 61.096,123.904 61.666,123.334 JP2.2@61.666,121.919
  Top Layer w0.45: v1(2.541,113.779) 2.956,114.194 v1(2.966,114.204)
  Top Layer w0.5: v1(1.941,113.179) v1(2.541,113.779) ; v1(2.141,11.204) 2.141,10.554 v1(2.116,10.529) v1(1.366,10.529) ; v1@2.956,114.194 2.966,114.194 2.966,113.804 ; U18.5@27.736,13.229 U18.5@27.741,13.224 ; U11.6@60.298,108.076 61.813,108.076 C40.2@61.816,108.079 R25.2@63.016,108.079 ; v1(1.366,10.529) v1(1.366,11.204) 2.041,11.204 v1(1.366,10.529) ; 2.391,113.229 2.966,113.804 ; 2.391,113.229 2.004,113.229 1.954,113.179 2.341,113.179 2.391,113.229 ; 2.391,113.229 v1(2.966,113.229) 2.966,113.804 ; v1(25.966,13.229) 25.966,13.829 v1(26.066,13.929) v1(26.666,13.929) ; v1(25.966,13.229) 26.166,13.229 v1(26.666,13.229) v1(26.666,13.929) ; v1(25.966,13.229) 26.066,13.329 v1(26.666,13.929)
  Top Layer w0.8: v1(26.066,13.929) 26.066,13.329 v1@26.166,13.229 ; v1(26.666,13.229) U18.5@27.736,13.229
  Top Layer w1: CN11.18@5.786,81.279 5.802,81.295 10.85,81.295 CN8.9@10.866,81.279
  Top Layer w1.5: JP2.8@61.666,114.299 JP2.6@61.666,116.839 JP2.4@61.666,119.379 JP2.2@61.666,121.919
  Signal Layer 2 w0.5: v1(1.941,113.179) v1@1.966,113.179 ; v1(26.666,13.229) v1(25.966,13.229) ; 40.541,118.429 40.516,118.429 ; v1@1.466,10.529 2.116,11.179 v1(2.116,10.529) v1@1.466,10.529 ; v1@1.466,10.529 v1(1.366,10.529) v1(1.366,11.204) v1(2.141,11.204) 15.441,11.204 17.466,13.229 v1(25.966,13.229) ; v1@1.966,113.179 1.966,113.204 v1(2.541,113.779) ; v1@1.966,113.179 2.916,113.179 v1(2.966,113.229) v1@2.966,113.354 ; v1(2.541,113.779) 2.541,114.979 2.966,115.404 ; v1(2.541,113.779) v1(2.966,114.204) ; v1(2.541,113.779) v1@2.966,113.354 ; v1@2.966,113.354 v1(2.966,114.204) ; v1(2.966,114.204) 2.966,115.404 ; 2.966,115.404 6.216,118.654 12.941,118.654 13.466,119.179 15.491,119.179 16.191,118.479 22.141,118.479 23.541,117.079 38.216,117.079 38.941,117.804 ; v1(25.966,13.229) 25.966,13.829 v1(26.066,13.929) ; v1(26.066,13.929) 26.666,13.329 v1(26.666,13.929) v1(26.066,13.929) ; 38.941,117.804 39.566,118.429 ; 38.941,117.804 38.941,118.429 ; 38.941,118.429 39.566,118.429 ; 38.941,118.429 38.941,119.054 ; 38.941,119.054 39.566,118.429 ; 38.941,119.054 39.466,119.054 ; 39.466,119.054 39.891,119.054 40.516,118.429 ; 39.466,119.054 40.091,118.429 ; 39.566,118.429 40.091,118.429 ; 40.091,118.429 40.516,118.429
  Signal Layer 2 w1: CN11.18@5.786,81.279 5.802,81.295 10.85,81.295 CN8.9@10.866,81.279
  Signal Layer 2 w1.5: JP2.8@61.666,114.299 JP2.6@61.666,116.839 JP2.4@61.666,119.379 JP2.2@61.666,121.919
  Signal Layer 3 w0.4: 1.941,90.179 1.951,90.169 6.347,90.169 ; 2.286,80.009 3.807,80.009 ; 2.401,77.469 6.347,77.469 ; 2.685,87.629 7.416,87.629 7.441,87.654
  Signal Layer 3 w0.5: 2.286,80.009 1.946,80.009 1.366,79.429 1.366,77.454 ; 2.401,77.469 1.381,77.469 1.366,77.454 ; 2.685,87.629 2.366,87.629 1.941,88.054 1.941,90.179 v1(1.941,113.179) v1@1.991,113.229 ; v1@2.941,113.254 2.541,113.654 v1(2.541,113.779) ; 3.807,80.009 4.516,80.009 CN11.18@5.786,81.279 ; 6.347,77.469 6.731,77.469 7.391,78.129 7.391,79.674 CN11.18@5.786,81.279 ; 6.347,90.169 6.726,90.169 7.416,89.479 7.416,87.629 7.416,82.909 CN11.18@5.786,81.279 ; v1(1.366,11.204) 1.366,11.979 ; v1(1.366,11.204) v1(2.141,11.204) 1.366,11.979 ; v1(1.366,11.204) v1(1.366,10.529) v1@1.466,10.529 ; 1.366,11.979 1.366,77.454 ; v1@1.466,10.529 2.116,11.179 v1(2.116,10.529) v1@1.466,10.529 ; v1@1.991,113.229 v1(2.966,113.229) v1(2.966,114.204) v1(2.541,113.779) ; v1@1.991,113.229 v1(2.541,113.779) ; v1(26.066,13.929) v1@26.666,13.329 ; v1(26.066,13.929) 25.966,13.829 v1(25.966,13.229) v1(26.666,13.229) v1@26.666,13.329 ; v1(26.066,13.929) v1(26.666,13.929) v1@26.666,13.329
  Signal Layer 3 w1.5: JP2.8@61.666,114.299 JP2.2@61.666,121.919
  Bottom Layer w0.5: v1(2.141,11.204) v1(1.366,11.204) v1(1.366,10.529) v1@1.491,10.529 ; v1(26.066,13.929) 25.966,13.829 v1(25.966,13.229) v1(26.666,13.229) v1@26.666,13.354 ; v1@1.491,10.529 2.116,11.154 v1(2.116,10.529) v1@1.491,10.529 ; v1(2.541,113.779) v1(2.966,114.204) v1(2.966,113.229) ; v1(2.541,113.779) v1(1.941,113.179) 2.916,113.179 v1(2.966,113.229) ; v1(2.541,113.779) 2.541,113.654 v1(2.966,113.229) ; v1@26.666,13.354 26.091,13.929 v1(26.666,13.929) v1@26.666,13.354
  Bottom Layer w1.5: JP2.8@61.666,114.299 JP2.2@61.666,121.919
5V_EXT: CN11.6 D2.1 JP2.5 | length 82.2
  Top Layer w0.8: v1(7.541,108.904) v1(8.741,108.904) 25.641,108.904 26.191,108.354 31.991,108.354 35.221,111.584 50.421,111.584 55.676,116.839 JP2.5@59.126,116.839
  Signal Layer 3 w0.8: 7.541,98.274 8.575,97.24 8.575,96.025 7.905,95.355 6.95,95.355 CN11.6@5.786,96.519 7.541,98.274 ; 7.541,98.274 7.541,107.704 ; 7.541,107.704 v1(8.741,108.904) v1(7.541,108.904) 7.541,107.704
  Bottom Layer w1: D2.1@54.481,116.839 JP2.5@59.126,116.839
5V_USB_CHGR: C3.2 C6.2 CN1.1 D3.1 JP2.7 R1.2 R2.2 U2.5 U6.1 | length 20.7
  Top Layer w0.4: U2.5@40.866,128.014 U2.5@40.866,128.229 ; C3.2@42.394,128.229 C3.2@42.396,128.227 ; CN1.1@50.266,129.158 50.266,128.626 51.249,127.643 C6.2@51.249,127.593 51.399,127.443 U6.1@51.399,126.293 U6.1@51.399,125.946 ; U6.1@51.399,125.946 v1(51.899,125.446) v1(51.399,125.446) U6.1@51.399,125.946
  Top Layer w0.5: v1(36.498,129.324) 36.503,129.329 R1.2@37.325,129.329 37.325,128.507 v1(37.33,128.502) ; U2.5@40.866,128.229 C3.2@42.394,128.229 ; v1(42.401,127.401) 42.396,127.406 C3.2@42.396,128.227 43.218,128.227 v1(43.223,128.232) ; v1(61.066,127.279) R2.2@62.091,127.279 ; v1(62.091,126.254) R2.2@62.091,127.279 ; v1(63.116,127.279) R2.2@62.091,127.279
  Signal Layer 1 w0.4: v1@51.416,125.429 51.433,125.446 v1(51.899,125.446)
  Signal Layer 2 w0.4: v1(51.399,125.446) v1(51.899,125.446)
  Signal Layer 3 w0.4: v1(51.399,125.446) v1(51.899,125.446)
  Signal Layer 4 w0.4: v1(51.399,125.446) v1(51.899,125.446)
  Bottom Layer w0.4: v1(51.399,125.446) v1(51.899,125.446)
  Bottom Layer w1: D3.1@54.481,114.299 JP2.7@59.126,114.299
5V_USB_STLK: C1.2 CN12.8 JP2.1 U2.1 | length 65.7
  Top Layer w0.508: U2.1@40.866,130.214 40.866,131.537 C1.2@41.148,131.82 41.525,131.82 ; 41.525,131.82 v1@42.041,131.82 ; 41.525,131.82 v1(42.041,131.304) v1@42.041,131.82 ; v1@42.041,131.82 42.05,131.82 v1(42.041,131.829) v1@42.041,131.82
  Bottom Layer w0.5: v1(42.041,131.304) 43.516,131.304 44.591,130.229 44.591,128.229 47.016,125.804 48.566,125.804 49.071,125.299 49.071,123.724 50.876,121.919 JP2.1@59.126,121.919
  Bottom Layer w0.508: v1(42.041,131.304) v1(42.041,131.829)
  Bottom Layer w0.8: JP2.1@59.126,121.919 59.126,123.126 59.679,123.679 63.046,123.679 64.025,122.7 64.025,121.145 68.516,116.654 68.516,95.504 66.966,93.954 CN12.8@66.746,93.954
5V_VIN: C41.2 D1.1 JP2.3 U12.2 U12.4 | length 57.8
  Top Layer w0.8: C41.2@16.541,104.074 U12.2@18.246,104.074
  Top Layer w1: U12.2@18.246,104.074 U12.2@18.266,104.054 v1(19.641,104.054) v1(20.691,104.054) v1(23.166,104.054) U12.4@24.616,104.054
  Signal Layer 2 w1: v1(20.666,107.479) 20.716,107.529 v1(23.241,107.529) v1(25.466,107.529) 26.191,108.254 31.866,108.254 34.591,110.979 42.341,110.979 45.716,114.354 45.716,117.204 47.891,119.379 JP2.3@59.126,119.379
  Bottom Layer w1: D1.1@54.481,119.379 JP2.3@59.126,119.379
  other v1: 20.641,100.579 23.291,100.579 25.566,100.629 20.666,102.129 23.216,102.129 21.841,104.079 23.266,105.879 20.666,105.904
AGND: C58.1 C64.2 C65.1 C66.2 C67.1 CN10.3 CN12.32 SB43.2 U14.31 | length 64.9
  Top Layer w0.3: v1(40.55,62.25) 41.366,61.434 U14.31@41.366,60.479 41.366,59.409 42.4,58.375 C58.1@42.4,58.225 42.4,58.175 42.05,57.825 42.05,56.2 42.65,55.6 C64.2@42.8,55.6 C65.1@44.15,55.6 C67.1@45.275,55.6 C66.2@46.4,55.6 47.341,54.659 48.421,54.659 48.76,54.659 49.327,55.225 50.25,55.225 50.816,54.659 55.716,54.659 68.541,54.659 v1(68.55,54.65) ; CN10.3@56.586,71.119 57.876,69.829 67.321,69.829 68.322,68.828 v1(68.303,68.828) ; CN12.32@66.746,63.474 68.555,63.474 68.556,63.475 v1(68.553,63.478)
  Bottom Layer w0.3: v1(40.55,62.25) SB43.2@40.55,63.3 ; v1(68.303,68.828) 68.391,68.741 68.391,66.68 68.04,66.329 68.04,65.616 68.631,65.025 68.631,63.556 v1(68.553,63.478) ; v1@68.549,63.474 v1(68.553,63.478) ; v1(68.55,54.65) 68.525,54.65 68.631,54.756 68.631,63.4 v1(68.553,63.478)
ARD_D0_RX: CN10.16 SB66.1 SB68.2 | length 9.4
  Signal Layer 2 w0.12: v1(52.375,54.15) 52.875,54.65 57.897,54.65 CN10.16@59.126,55.879
  Bottom Layer w0.12: SB68.2@51.65,55.275 51.575,55.2 SB66.1@51.575,54.175 52.35,54.175 v1(52.375,54.15)
ARD_D1_TX: CN10.14 SB8.1 SB18.2 | length 48.9
  Top Layer w0.12: v1(50.238,88.988) 61.462,88.988 v1(61.875,88.575) ; CN10.14@59.126,58.419 59.957,59.25 v1(60.95,59.25)
  Bottom Layer w0.12: SB18.2@49.275,85.55 SB8.1@49.275,87.25 49.776,87.25 50.238,87.712 v1(50.238,88.988) ; v1(60.95,59.25) 60.755,59.445 60.755,62.739 60.6,62.894 60.6,67.338 60.325,67.613 60.325,69.352 61.181,70.208 61.181,72.05 60.82,72.411 60.82,72.843 61.421,73.444 61.421,77.781 61.07,78.132 61.07,79.194 61.571,79.695 61.571,87.466 61.875,87.77 v1(61.875,88.575)
BOOT0: CN11.7 R33.1 U14.138 | length 46
  Top Layer w0.155: v1(7.75,69.95) 8.325,70.525 16.525,70.525 18.475,68.575 20.161,68.575 21.425,67.311 R33.1@21.425,67.225 21.425,66.95 22.821,65.554 U14.138@24.291,65.554
  Bottom Layer w0.155: CN11.7@3.246,93.979 3.246,93.376 4.616,92.006 4.616,88.023 4.911,87.728 6.353,87.728 7.156,86.926 7.156,83.252 6.909,83.005 6.909,74.813 7.395,74.326 7.395,71.179 7.75,70.825 v1(7.75,69.95)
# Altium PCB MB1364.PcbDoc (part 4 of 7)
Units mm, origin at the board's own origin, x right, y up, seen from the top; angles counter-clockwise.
Board outline 70 x 133.34 mm, 6 copper layers (Top Layer, Signal Layer 1, Signal Layer 2, Signal Layer 3, Signal Layer 4, Bottom Layer), stack 1.57 mm thick; 320 components, 286 nets, 1370 pads, 2009 vias.

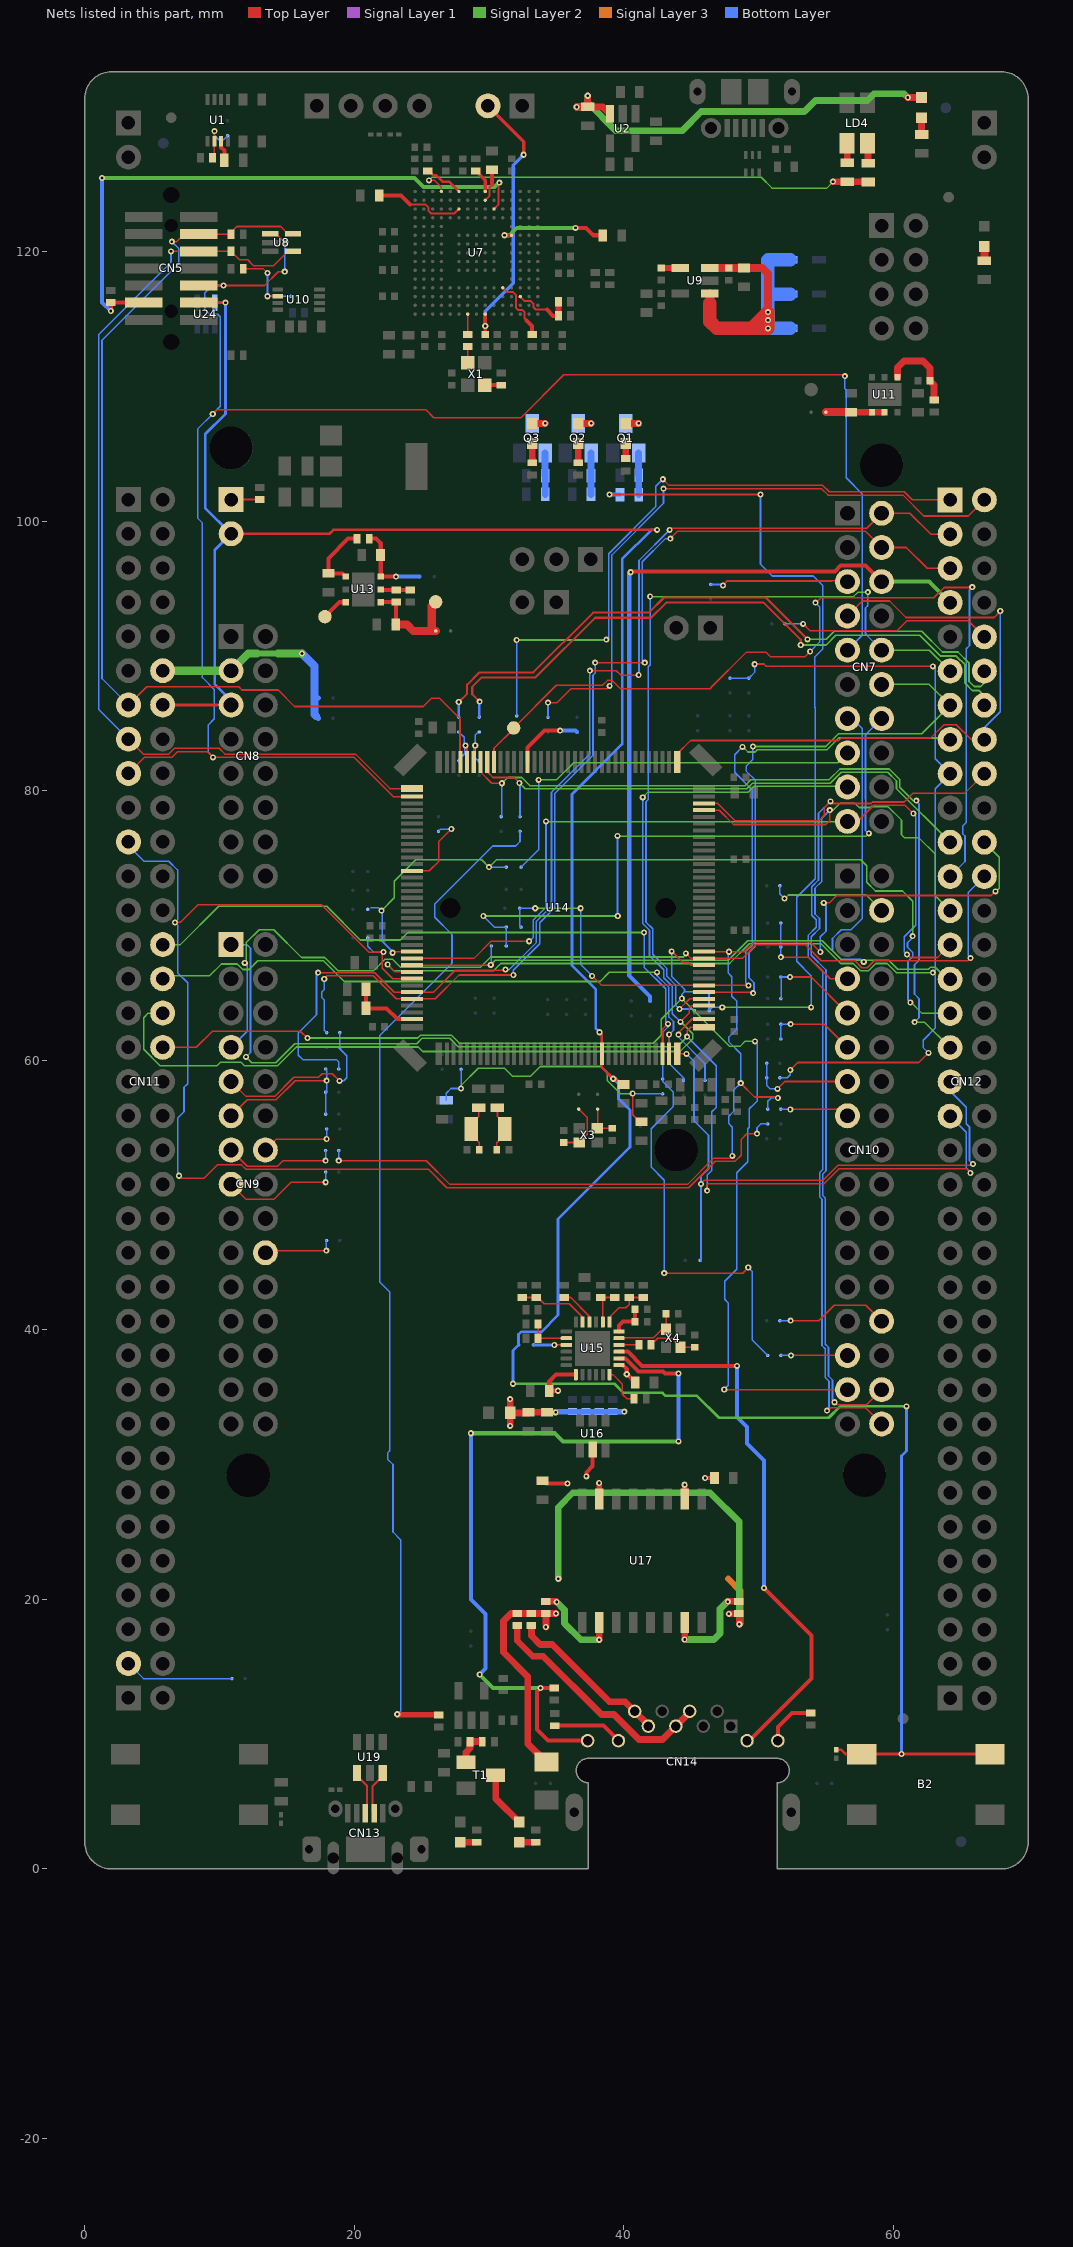
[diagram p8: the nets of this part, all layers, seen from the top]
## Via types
v1: diameter 0.45, hole 0.2, Top Layer to Bottom Layer, tented both sides, 1933 vias
v2: diameter 0.45, hole 0.2, Top Layer to Bottom Layer, tented top, 67 vias
v3: diameter 0.6, hole 0.3, Top Layer to Bottom Layer, tented both sides, 9 vias

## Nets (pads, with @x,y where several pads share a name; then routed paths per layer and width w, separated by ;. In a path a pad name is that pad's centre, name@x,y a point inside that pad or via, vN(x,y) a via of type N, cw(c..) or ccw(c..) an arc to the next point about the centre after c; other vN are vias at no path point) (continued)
GNDDetect: CN5.11 R17.2 U7.K13 | length 45.2
  Top Layer w0.15: U7.K13@30.366,123.154 30.691,123.479 30.691,125.029 v1(30.766,125.104)
  Top Layer w0.3: v1(1.941,115.579) R17.2@1.941,116.204 CN5.11@4.389,116.204
  Signal Layer 2 w0.3: v1(1.291,125.454) 24.466,125.454 25.136,124.784 30.396,124.784 30.741,125.129 v1(30.766,125.104)
  Bottom Layer w0.3: v1(1.291,125.454) 1.291,116.229 v1(1.941,115.579)
IOREF: CN8.3 CN11.12 SB11.2 SB20.2 | length 16.4
  Signal Layer 2 w0.45: 12.774,90.169 14.356,90.169
  Signal Layer 2 w0.6: CN11.12@5.786,88.899 CN8.3@10.866,88.899 12.136,90.169 12.774,90.169 ; 14.356,90.169 16.106,90.169 v1(16.116,90.179)
  Bottom Layer w0.4: 17.05,86.875 SB11.2@17.325,86.875 ; 17.175,85.525 SB20.2@17.325,85.375
  Bottom Layer w0.6: v1(16.116,90.179) 17.05,89.245 17.05,86.875 17.05,85.65 17.175,85.525
LED_STLK: R8.2 R9.2 U7.D15 | length 34.7
  Top Layer w0.12: v1(25.541,125.279) 25.952,125.279 26.466,124.764 U7.D15@26.466,124.454 ; R8.2@56.564,125.179 R8.2@56.566,125.177 ; R9.2@58.091,125.177 R9.2@58.116,125.152
  Top Layer w0.5: v1(55.516,125.179) R8.2@56.564,125.179 ; R8.2@56.566,125.177 R9.2@58.091,125.177
  Signal Layer 2 w0.12: v1(25.541,125.279) 25.771,125.509 50.184,125.509 50.989,124.704 55.066,124.704 55.541,125.179 v1(55.516,125.179)
NetC7_2: C7.2 U7.J14 | length 2.5
  Top Layer w0.15: U7.J14@29.716,123.804 30.036,124.124 30.036,124.774 30.216,124.954
  Top Layer w0.3: 30.216,124.954 C7.2@30.216,126.054
NetC12_2: C12.2 U7.F13 | length 6.8
  Top Layer w0.15: 24.141,123.479 24.146,123.484 25.289,123.484 25.496,123.276 25.496,123.021 25.694,122.824 27.436,122.824 U7.F13@27.766,123.154
  Top Layer w0.3: C12.2@21.841,124.154 23.466,124.154 24.141,123.479
NetC13_2: C13.2 U7.M10 | length 8.3
  Top Layer w0.25: v1(31.141,121.204) U7.M10@31.666,121.204
  Top Layer w0.3: v1(36.416,121.754) 37.191,121.754 37.741,121.204 C13.2@38.441,121.204
  Signal Layer 2 w0.3: v1(31.141,121.204) 31.516,121.204 31.903,121.591 32.066,121.754 v1(36.416,121.754)
NetC18_1: C18.1 C20.2 D1.2 D2.2 D3.2 U9.1 U9.3 | length 29.3
  Top Layer w0.45: C20.2@47.785,118.779 C20.2@47.794,118.77 ; C18.1@48.907,118.77 C18.1@48.916,118.779
  Top Layer w0.6: U9.3@46.391,118.779 C20.2@47.785,118.779 ; C20.2@47.794,118.77 C18.1@48.907,118.77 ; C18.1@48.916,118.779 50.266,118.779 50.691,118.354 v1(50.691,115.504)
  Top Layer w0.7: 46.391,116.154 U9.1@46.391,116.879
  Top Layer w1: 46.391,116.154 46.391,114.804 46.896,114.299 49.486,114.299 ; 49.486,114.299 v1(50.691,115.504) v1(50.691,114.904) v1(50.691,114.299) 49.486,114.299
  Signal Layer 2 w1: v1(50.691,114.299) v1(50.691,114.904) v1(50.691,115.504)
  Signal Layer 3 w1: v1(50.691,114.299) v1(50.691,114.904) v1(50.691,115.504)
  Bottom Layer w0.5: 50.691,119.354 50.716,119.379
  Bottom Layer w0.7: 50.691,116.779 50.751,116.839
  Bottom Layer w1: 50.691,119.354 50.691,116.779 v1(50.691,115.504) v1(50.691,114.904) v1(50.691,114.299) D3.2@52.341,114.299 ; 50.716,119.379 D1.2@52.341,119.379 ; 50.751,116.839 D2.2@52.341,116.839
NetC19_2: C19.2 U9.4 | length 1.4
  Top Layer w0.45: C19.2@42.791,118.779 U9.4@44.191,118.779
NetC28_2: C28.2 JP1.2 U7.J1 | length 20.1
  Top Layer w0.25: C28.2@29.716,113.854 v1(29.716,114.479) U7.J1@29.716,115.354 ; JP1.2@29.916,130.809 32.566,128.159 v1(32.566,127.179)
  Bottom Layer w0.25: v1(29.716,114.479) 29.716,115.579 31.791,117.654 31.791,126.404 v1(32.566,127.179)
NetC38_1: C38.1 R25.1 U11.1 | length 6
  Top Layer w0.5: U11.1@60.298,110.676 60.298,111.386 60.791,111.879 62.191,111.879 62.716,111.354 C38.1@62.716,110.404 63.016,110.104 R25.1@63.016,108.979
NetC39_2: C39.2 SB2.1 U11.4 U11.5 | length 4.4
  Top Layer w0.45: C39.2@56.866,108.079 56.869,108.076 U11.4@58.398,108.076 U11.5@59.348,108.076
  Top Layer w0.6: SB2.1@54.991,108.079 C39.2@56.866,108.079
NetC43_2: C43.2 R30.2 SB6.2 U13.6 | length 6.3
  Top Layer w0.3: R30.2@21.116,98.704 21.616,98.704 21.966,98.354 U13.6@21.966,95.879 v1(23.091,95.879)
  Bottom Layer w0.3: v1(23.091,95.879) SB6.2@24.841,95.879
NetC44_2: C44.2 R30.1 U13.1 | length 5.3
  Top Layer w0.3: U13.1@19.366,95.879 19.12,96.125 C44.2@18.075,96.125 18.075,97.238 19.541,98.704 R30.1@20.216,98.704
NetC45_2: C45.2 R31.2 SB80.1 TP2.1 U13.4 | length 8.2
  Top Layer w0.3: U13.4@21.99,94.01 23.09,94.01 R31.2@23.1,94 23.1,93.361 23.099,93.36 C45.2@23.099,92.356
  Top Layer w0.6: C45.2@23.075,92.325 23.9,92.325 24.375,91.85 25.75,91.85 ; TP2.1@26.041,94.004 25.75,93.713 25.75,91.85 ; SB80.1@26.05,91.85 25.75,91.85
NetC68_2: C68.2 R74.1 SB51.1 SB58.1 | length 23.1
  Top Layer w0.12: v1(40.65,57.525) 40.65,55.95 41.175,55.425 C68.2@41.325,55.425
  Signal Layer 2 w0.12: v1(27.925,57.9) 27.925,58.123 29.207,59.405 31.145,59.405 31.75,58.8 33.06,58.8 33.792,59.532 38.343,59.532 38.775,59.1 38.775,58.491 39.74,57.525 v1(40.65,57.525)
  Bottom Layer w0.12: R74.1@26.825,57.025 26.825,57.55 27.175,57.9 v1(27.925,57.9) SB51.1@27.925,59.325 ; v1(40.65,57.525) 42.85,57.525 SB58.1@42.875,57.5
NetC74_2: C74.2 C76.2 U15.6 | length 2.7
  Top Layer w0.3: U15.6@39.641,39.879 39.641,40.304 39.941,40.604 C76.2@40.841,40.604 C74.2@40.841,41.529
NetC75_2: C75.2 U15.5 X4.3 | length 4.9
  Top Layer w0.12: U15.5@39.641,39.379 39.641,39.409 42.196,39.409 42.841,40.054 X4.3@43.141,40.054 C75.2@43.141,41.179
NetC77_2: C77.2 R50.1 X4.1 | length 3.8
  Top Layer w0.12: R50.1@42.016,38.879 42.516,39.379 43.566,39.379 44.191,38.754 X4.1@44.191,38.704 C77.2@45.266,38.704
NetC78_2: C78.2 C79.1 C80.2 C81.2 C82.2 C83.2 L1.1 R75.2 R76.2 R77.2 R78.2 U15.1 U15.19 U16.5 U17.2 U17.7 | length 23.1
  Top Layer w0.3: C83.2@33.95,28.875 34.234,28.591 35.121,28.591 v1(35.821,28.591) ; v1(35.116,35.479) C79.1@34.466,35.479 34.466,36.179 34.966,36.679 U15.19@36.441,36.679 ; v1(37.216,29.129) 37.216,29.404 37.691,29.879 U16.5@37.691,31.129 ; U15.1@39.641,37.379 39.916,37.379 40.216,37.079 v1(40.216,36.704) C78.2@40.841,36.079 ; v1(46.029,29.009) C82.2@46.729,29.009
  Top Layer w0.4: v1@38.15,28.575 38.171,28.554 U17.7@38.171,27.434 ; U17.2@44.521,27.434 44.525,27.438 v1@44.525,28.45
  Top Layer w0.5: v1(31.565,32.875) 31.565,33.875 L1.1@31.566,33.874 ; L1.1@31.566,33.854 L1.1@31.566,33.874 ; v1(31.566,34.854) L1.1@31.566,33.874 ; v1(34.941,33.879) C81.2@34.291,33.879 33.021,33.879 32.975,33.832 31.608,33.832 L1.1@31.566,33.874
  Bottom Layer w0.4: v1(34.941,33.879) 34.991,33.929 R78.2@36.191,33.929 R77.2@37.191,33.929 R76.2@38.191,33.929 R75.2@39.191,33.929 v1(40.041,33.929)
  other v1: 44.516,28.504 38.166,28.629
NetC85_2: C85.2 R52.1 R53.1 R54.1 R55.1 | length 50.1
  Top Layer w0.3: R52.1@34.141,18.904 R52.1@34.191,18.954 R52.1@34.216,18.929 ; R53.1@48.516,18.979 48.566,18.929 R53.1@48.616,18.979
  Top Layer w0.5: v1(34.216,17.954) R52.1@34.216,18.929 ; C85.2@34.25,7.925 32.866,9.309 32.866,14.279 31.066,16.079 31.066,18.4 31.62,18.954 R54.1@32.091,18.954 R55.1@33.141,18.954 R52.1@34.191,18.954 v1(34.966,18.954) ; v1(47.791,18.929) 48.566,18.929 v1(48.566,18.154)
  Signal Layer 2 w0.5: v1(35.141,21.529) 35.141,26.837 36.212,27.909 46.391,27.909 48.566,25.734 v1(48.566,18.154)
  Signal Layer 3 w0.5: 47.746,21.529 48.625,20.65 48.625,18.213 v1(48.566,18.154)
NetCN7_5: CN7.5 SB7.2 | length 10.3
  Top Layer w0.127: v1(47.35,95.225) 47.685,95.56 55.425,95.56 55.435,95.57 56.519,95.57 CN7.5@56.586,95.503
  Bottom Layer w0.127: SB7.2@46.45,95.3 47.275,95.3 v1(47.35,95.225)
NetCN7_6: CN7.6 CN12.7 SB42.1 | length 57.5
  Top Layer w0.3: v1(40.505,96.205) 40.575,96.275 55.668,96.275 56.091,96.698 57.931,96.698 CN7.6@59.126,95.503
  Signal Layer 2 w0.3: CN7.6@59.126,95.503 62.657,95.503 CN12.7@64.206,93.954
  Bottom Layer w0.3: v1(40.505,96.205) 40.4,96.1 40.4,66.275 41.95,64.725 SB42.1@41.95,64.4
NetCN7_14: CN7.14 SB33.1 SB35.1 | length 47.4
  Signal Layer 2 w0.12: v1(29.575,70.7) v1(39.55,70.7) ; v1(39.525,76.65) 39.5,76.625 56.121,76.625 56.128,76.618 57.967,76.618 v1(58.178,76.829)
  Bottom Layer w0.12: v1(29.575,70.7) 30.4,69.875 SB33.1@31.275,69.875 SB35.1@31.275,68.475 ; v1(39.525,76.65) 39.525,70.725 v1(39.55,70.7) ; v1(58.178,76.829) 58.175,76.826 58.175,76.8 57.931,77.044 57.931,78.883 57.935,78.887 57.935,79.345 57.931,79.349 57.931,84.148 CN7.14@59.126,85.343
NetCN7_15: CN7.15 SB26.2 | length 30.8
  Signal Layer 2 w0.12: v1(33.677,80.804) 33.681,80.8 35,80.8 36.28,82.08 55.863,82.08 CN7.15@56.586,82.803
  Signal Layer 3 w0.12: v1@33.677,80.802 v1(33.677,80.804)
  Bottom Layer w0.12: SB26.2@32.375,74.325 33.677,75.627 v1(33.677,80.804)
NetCN9_9: CN9.9 SB53.2 SB55.2 | length 13.6
  Top Layer w0.12: CN9.9@10.866,58.419 11.971,57.314 14.099,57.314 15.513,58.728 17.352,58.728 17.625,59 18.375,59 v1(18.9,58.475)
  Bottom Layer w0.12: v1(18.9,58.475) 19.225,58.475 19.45,58.7 19.45,60.325 18.925,60.85 SB53.2@18.925,60.95 SB55.2@18.925,62.05
NetCN9_11: CN9.11 SB60.2 SB62.2 SB65.2 | length 11.6
  Top Layer w0.12: CN9.11@10.866,55.879 12.061,57.074 14.198,57.074 15.612,58.488 v1(17.95,58.488)
  Bottom Layer w0.12: SB60.2@17.875,56 SB65.2@17.875,57.625 17.95,57.7 v1(17.95,58.488) 17.95,59.275 SB62.2@17.875,59.35
NetCN9_13: CN9.13 SB69.2 | length 8.4
  Top Layer w0.12: CN9.13@10.866,53.339 12.061,52.144 14.3,52.144 14.706,52.55 v1(17.875,52.55)
  Bottom Layer w0.12: v1(17.875,52.55) SB69.2@17.875,53.3
NetCN9_14: CN9.14 SB67.1 | length 5.6
  Top Layer w0.12: CN9.14@13.406,53.339 14.217,54.15 v1(17.95,54.15)
  Bottom Layer w0.12: v1(17.95,54.15) SB67.1@17.95,54.9
NetCN9_15: CN9.15 SB70.2 | length 8.7
  Top Layer w0.12: CN9.15@10.866,50.799 11.971,49.694 14.044,49.694 15.3,50.95 v1(17.875,50.95)
  Bottom Layer w0.12: v1(17.875,50.95) SB70.2@17.875,51.7
NetCN9_20: CN9.20 SB71.1 | length 5.3
  Top Layer w0.12: CN9.20@13.406,45.719 13.562,45.875 v1(17.925,45.875)
  Bottom Layer w0.12: v1(17.925,45.875) SB71.1@17.925,46.625
NetCN10_4: CN10.4 SB28.1 | length 8.9
  Signal Layer 2 w0.12: v1(51.925,72) 51.925,71.975 52.212,72.262 57.983,72.262 CN10.4@59.126,71.119
  Bottom Layer w0.12: SB28.1@51.575,72.944 51.575,72.35 v1(51.925,72)
NetCN10_7: CN10.7 SB37.2 SB38.2 | length 8.1
  Top Layer w0.12: v1(51.65,67.65) 53.704,67.65 55.316,66.039 CN10.7@56.586,66.039
  Bottom Layer w0.12: v1(51.65,67.65) SB38.2@51.65,68.4 SB37.2@51.65,70.175
NetCN10_9: CN10.9 SB48.2 SB49.2 | length 7.7
  Top Layer w0.127: v1(52.325,66.175) 53.91,66.175 CN10.9@56.586,63.499
  Bottom Layer w0.127: SB49.2@51.65,64.575 51.687,64.612 SB48.2@51.687,66.175 ; SB48.2@51.65,66.175 SB48.2@51.687,66.175 ; v1(52.325,66.175) SB48.2@51.687,66.175
NetCN10_11: CN10.11 SB50.2 SB54.2 | length 6.7
  Top Layer w0.127: v1(52.375,62.675) 54.87,62.675 CN10.11@56.586,60.959
  Bottom Layer w0.127: SB54.2@51.65,61.575 SB50.2@51.65,62.675 v1(52.375,62.675)
NetCN10_13: CN10.13 SB59.2 SB61.2 | length 8
  Top Layer w0.12: v1(51.4,57.875) 51.944,58.419 CN10.13@56.586,58.419
  Bottom Layer w0.12: SB59.2@50.6,59.775 SB61.2@50.6,58.7 50.6,58.125 50.85,57.875 v1(51.4,57.875)
NetCN10_15: CN10.15 SB63.2 | length 5.1
  Top Layer w0.12: v1(52.35,56.35) 56.115,56.35 CN10.15@56.586,55.879
  Bottom Layer w0.12: SB63.2@51.65,56.375 52.325,56.375 v1(52.35,56.35)
NetCN10_28: CN10.28 SB73.1 | length 8.5
  Top Layer w0.12: v1(52.375,40.675) 54.45,40.675 55.6,41.825 57.94,41.825 CN10.28@59.126,40.639
  Bottom Layer w0.12: SB73.1@51.575,40.675 v1(52.375,40.675)
NetCN10_29: CN10.29 SB75.2 | length 4.9
  Top Layer w0.12: v1(52.399,38.099) CN10.29@56.586,38.099
  Bottom Layer w0.12: SB75.2@51.65,38.1 52.398,38.1 v1(52.399,38.099)
NetCN11_69: CN11.69 SB81.2 | length 8.1
  Bottom Layer w0.12: CN11.69@3.246,15.239 4.36,14.125 SB81.2@10.925,14.125
NetCN12_1: CN12.1 SB15.2 | length 47.9
  Top Layer w0.12: v1(38.702,91.204) 38.704,91.204 v1@38.729,91.179 ; v1(42.891,103.104) 43.351,102.644 54.765,102.644 55.241,102.168 60.806,102.168 61.4,101.574 CN12.1@64.206,101.574
  Signal Layer 2 w0.12: v1(32.052,91.179) v1@38.729,91.179
  Bottom Layer w0.12: SB15.2@32.05,85.55 v1(32.052,91.179) v1(32.052,91.179) ; v1(38.702,91.204) 38.875,91.378 38.875,97.586 42.375,101.086 42.375,102.588 v1(42.891,103.104)
NetCN12_2: CN12.2 SB14.1 | length 47.6
  Top Layer w0.12: v1(34.375,86.525) 35.036,86.525 36.081,87.57 38.745,87.57 v1(38.95,87.775) ; v1(42.943,102.406) 42.941,102.404 54.666,102.404 55.142,101.928 60.706,101.928 62.255,100.379 65.551,100.379 CN12.2@66.746,101.574
  Bottom Layer w0.12: SB14.1@34.375,85.45 v1(34.375,86.525) ; v1(38.95,87.775) 38.95,87.85 39.115,88.015 39.115,97.487 42.943,101.315 v1(42.943,102.406)
NetCN12_10: CN12.10 SB82.1 | length 15.8
  Top Layer w0.12: v1(53.3,92.375) 53.817,91.858 60.258,91.858 61.009,92.609 65.551,92.609 CN12.10@66.746,91.414
  Bottom Layer w0.12: SB82.1@51.95,92.375 v1(53.3,92.375)
NetCN12_12: CN12.12 SB17.1 | length 48.7
  Top Layer w0.155: v1(27.75,86.575) 28.369,87.194 28.369,87.858 29.292,88.781 33.292,88.781 37.717,93.206 41.856,93.206 42.981,94.331 50.526,94.331 v1(53.628,91.229)
  Signal Layer 2 w0.13: v1(53.628,91.229) 55.004,91.229 55.608,91.833 62.088,91.833 63.637,90.284 64.79,90.284 65.616,89.458 65.616,88.1 65.991,87.725 66.475,87.725 66.746,87.996 CN12.12@66.746,88.874
  Bottom Layer w0.155: SB17.1@27.75,85.45 v1(27.75,86.575)
NetCN12_14: CN12.14 SB16.1 | length 48.3
  Top Layer w0.155: v1(29.3,86.6) 28.75,87.15 28.75,87.7 29.45,88.4 33.45,88.4 37.875,92.825 42.014,92.825 43.139,93.95 50.368,93.95 53.125,91.193 v1(53.125,90.8)
  Signal Layer 2 w0.13: v1(53.125,90.8) 54.999,90.8 55.732,91.533 61.964,91.533 63.513,89.984 64.666,89.984 65.316,89.334 65.316,87.976 65.867,87.425 66.375,87.425 66.746,87.054 CN12.14@66.746,86.334
  Bottom Layer w0.12: SB16.1@29.275,85.45 SB16.1@29.3,85.475
  Bottom Layer w0.155: SB16.1@29.275,85.45 29.275,86.575 v1(29.3,86.6)
NetCN13_2: CN13.2 U19.6 | length 3.4
  Top Layer w0.155: CN13.2@21.473,4.139 21.338,4.273 21.338,6.122 22.116,6.9 U19.6@22.116,7.129
NetCN13_3: CN13.3 U19.4 | length 3.4
  Top Layer w0.155: U19.4@20.216,7.129 20.216,6.9 20.957,6.158 20.957,4.273 CN13.3@20.823,4.139
NetCN14_4: CN14.4 CN14.5 R54.2 | length 17.9
  Top Layer w0.5: R54.2@32.091,18.054 32.091,16.929 33.241,15.779 34.016,15.779 38.341,11.454 39.266,11.454 41.116,9.604 42.863,9.604 CN14.5@43.859,10.6 44.879,11.62 CN14.4@44.879,11.7
NetCN14_7: CN14.7 CN14.8 R55.2 | length 12.3
  Top Layer w0.5: R55.2@33.141,18.054 33.141,17.304 33.791,16.654 34.691,16.654 38.941,12.404 40.095,12.404 CN14.8@40.799,11.7 41.819,10.68 CN14.7@41.819,10.6
NetCN14_9: CN14.9 R58.2 | length 3.9
  Top Layer w0.3: CN14.9@51.429,9.52 51.429,10.516 52.491,11.579 R58.2@53.866,11.579
NetCN14_10: CN14.10 U15.3 | length 41.4
  Top Layer w0.3: U15.3@39.641,38.379 40.291,38.379 41.341,37.329 48.396,37.329 v1(48.4,37.325) ; CN14.10@49.139,9.52 49.32,9.52 53.925,14.125 53.925,17.325 v1(50.4,20.85)
  Bottom Layer w0.3: v1(48.4,37.325) 48.4,33.526 49.135,32.792 49.135,31.565 50.4,30.3 v1(50.4,20.85)
NetCN14_11: CN14.11 R59.2 | length 5.2
  Top Layer w0.3: R59.2@34.866,10.629 38.489,10.629 CN14.11@39.599,9.52
NetCN14_12: CN14.12 R57.2 U15.2 | length 57.4
  Top Layer w0.3: R57.2@34.841,13.423 34.835,13.429 v1(33.816,13.429) 33.541,13.154 33.541,10.354 34.375,9.52 CN14.12@37.309,9.52 ; U15.2@39.641,37.879 40.116,37.879 41.091,36.904 42.891,36.904 43.041,36.754 v1(44.05,36.754)
  Signal Layer 2 w0.3: v1(28.65,32.325) 34.875,32.325 35.475,31.725 v1(44.05,31.725) ; v1(29.3,14.425) 30.296,13.429 v1(33.816,13.429)
  Bottom Layer w0.3: v1(28.65,32.325) 28.65,20 29.75,18.9 29.75,14.875 v1(29.3,14.425) ; v1(44.05,31.725) v1(44.05,36.754)
NetJP3_1: JP3.1 R29.2 | length 2.1
  Top Layer w0.12: JP3.1@10.866,101.599 10.871,101.604 R29.2@12.991,101.604
NetLD1_1: LD1.1 R26.1 | length 1.1
  Top Layer w0.5: R26.1@40.141,104.629 LD1.1@40.141,105.747
NetLD1_2: LD1.2 Q1.3 | length 1.9
  Top Layer w0.5: LD1.2@40.141,107.247 41.092,107.247 v1(41.099,107.254)
  Bottom Layer w0.5: Q1.3@40.141,107.247 41.092,107.247 v1(41.099,107.254)
NetLD2_1: LD2.1 R28.1 | length 1.2
  Top Layer w0.5: R28.1@36.616,104.579 LD2.1@36.616,105.747
NetLD2_2: LD2.2 Q2.3 | length 1.9
  Top Layer w0.5: LD2.2@36.616,107.247 37.567,107.247 v1(37.574,107.254)
  Bottom Layer w0.5: Q2.3@36.616,107.247 37.567,107.247 v1(37.574,107.254)
NetLD3_1: LD3.1 R27.1 | length 1.2
  Top Layer w0.5: LD3.1@33.208,105.747 33.208,104.587 R27.1@33.216,104.579
NetLD3_2: LD3.2 Q3.3 | length 1.9
  Top Layer w0.5: LD3.2@33.208,107.247 34.159,107.247 v1(34.166,107.254)
  Bottom Layer w0.5: Q3.3@33.208,107.247 34.159,107.247 v1(34.166,107.254)
NetLD4_2: LD4.2 R9.1 | length 1.5
  Top Layer w0.5: LD4.2@58.066,128.029 58.116,127.979 R9.1@58.116,126.552
NetLD4_3: LD4.3 R8.1 | length 1.5
  Top Layer w0.5: R8.1@56.566,126.577 LD4.3@56.566,128.029
NetLD5_1: LD5.1 R12.1 | length 1
  Top Layer w0.6: R12.1@66.746,119.319 LD5.1@66.746,120.369
NetLD6_1: LD6.1 R2.1 | length 1.2
  Top Layer w0.5: R2.1@62.091,128.679 LD6.1@62.091,129.929
NetLD6_2: LD6.2 R1.1 U2.3 | length 31.9
  Top Layer w0.5: v1(36.498,130.724) 36.503,130.729 R1.1@37.325,130.729 ; v1(37.32,131.555) 37.325,131.55 R1.1@37.325,130.729 ; U2.3@38.966,130.214 38.451,130.729 R1.1@37.325,130.729 ; v1(61.066,131.429) LD6.2@62.091,131.429
  Signal Layer 2 w0.5: v1(36.498,130.724) 36.986,130.724 37.32,131.058 ; v1(37.32,131.555) 37.32,131.058 ; v1(61.066,131.429) 60.791,131.704 58.557,131.704 58.057,131.204 54.216,131.204 53.391,130.379 45.741,130.379 44.316,128.954 39.424,128.954 37.32,131.058
NetLD7_1: LD7.1 R65.1 | length 1.2
  Top Layer w0.5: LD7.1@27.866,1.979 R65.1@29.091,1.979
NetLD8_1: LD8.1 R66.1 | length 1.2
  Top Layer w0.5: LD8.1@32.241,1.979 R66.1@33.466,1.979
NetLD8_2: LD8.2 T1.3 | length 4.2
  Top Layer w0.5: T1.3@30.491,6.954 30.491,5.229 LD8.2@32.241,3.479
NetQ1_1: Q1.1 R68.2 R73.2 | length 3.1
  Bottom Layer w0.5: Q1.1@41.091,105.047 41.091,103.405 R68.2@41.111,103.385 41.114,103.382 R73.2@41.114,101.967
NetQ2_1: Q2.1 R69.2 R71.2 | length 3.1
  Bottom Layer w0.5: R71.2@37.566,101.979 R69.2@37.566,103.379 Q2.1@37.566,105.047
NetQ3_1: Q3.1 R70.2 R72.2 | length 3.1
  Bottom Layer w0.5: Q3.1@34.158,105.047 34.158,103.387 R70.2@34.166,103.379 R72.2@34.166,101.979
NetR3_2: R3.2 SB1.1 U1.6 | length 3.6
  Top Layer w0.12: R3.2@9.491,126.954 9.616,127.079 U1.6@9.616,128.179 9.616,128.916 v1(9.625,128.925)
  Bottom Layer w0.12: v1(9.625,128.925) 9.625,128.625 9.95,128.3 10.3,128.3 SB1.1@10.6,128.6
NetR4_2: R4.2 U1.7 | length 1.5
  Top Layer w0.3: U1.7@10.116,128.179 10.116,127.729 10.366,127.479 R4.2@10.366,126.779
NetR5_1: R5.1 U7.F15 | length 2.9
  Top Layer w0.2: R5.1@25.466,125.979 25.566,125.979 25.891,125.654 26.086,125.654 26.561,125.179 27.041,125.179 U7.F15@27.766,124.454
NetR6_2: R6.2 U7.J15 | length 1.8
  Top Layer w0.25: R6.2@29.016,125.979 29.716,125.279 U7.J15@29.716,124.454
NetR13_2: R13.2 SB5.2 U10.6 | length 6.1
  Top Layer w0.12: R13.2@11.766,118.729 11.786,118.709 13.261,118.709 v1(13.566,118.404) ; v1(13.566,116.679) U10.6@14.316,116.679
  Bottom Layer w0.12: v1(13.566,118.404) v1(13.566,116.679) SB5.2@15.291,116.679
NetR18_1: R18.1 R20.1 U7.N3 | length 4.6
  Top Layer w0.15: U7.N3@32.316,116.654 32.646,116.324 33.099,116.324 33.286,116.136 33.286,115.881 33.484,115.684 34.296,115.684
  Top Layer w0.3: 34.296,115.684 34.751,115.229 R20.1@35.141,115.229
  Top Layer w0.45: R20.1@35.141,115.229 R18.1@35.141,116.279
NetR21_1: R21.1 X1.3 | length 1.2
  Top Layer w0.12: X1.3@28.416,111.729 R21.1@28.416,112.954
NetR21_2: R21.2 U7.G1 | length 1.5
  Top Layer w0.12: R21.2@28.416,113.854 U7.G1@28.416,115.354
NetR22_2: R22.2 U7.L4 | length 4.8
  Top Layer w0.15: U7.L4@31.016,117.304 31.341,116.979 31.794,116.979 31.991,116.782 31.991,115.829 32.146,115.674 32.449,115.674 32.636,115.486 32.636,115.034 32.791,114.879
  Top Layer w0.3: 32.791,114.879 33.191,114.479 R22.2@33.191,113.854
NetR24_2: R24.2 X1.1 | length 1.3
  Top Layer w0.3: X1.1@29.666,110.079 R24.2@30.916,110.079
NetR31_1: R31.1 R32.2 U13.5 | length 2.2
  Top Layer w0.3: U13.5@21.966,94.929 21.995,94.9 R31.1@23.1,94.9 R32.2@24.15,94.9
NetR34_1: R34.1 R35.1 U14.143 | length 5.1
  Top Layer w0.3: R35.1@20.875,65.25 R34.1@20.875,63.85 22.4,63.85 23.196,63.054 U14.143@24.291,63.054
NetR40_1: R40.1 R41.2 U15.11 | length 5.4
  Top Layer w0.127: R40.1@32.466,42.404 R41.2@33.516,42.404 33.616,42.404 34.091,41.929 35.941,41.929 36.941,40.929 U15.11@36.941,40.579
NetR42_1: R42.1 U15.10 | length 2.9
  Top Layer w0.127: R42.1@35.566,42.404 36.041,42.404 37.441,41.004 U15.10@37.441,40.579
NetR43_1: R43.1 R44.2 U15.8 | length 2.9
  Top Layer w0.127: U15.8@38.441,40.579 38.441,42.254 R43.1@38.291,42.404 R44.2@39.341,42.404
NetR45_2: R45.2 R46.1 U15.7 | length 3.8
  Top Layer w0.127: U15.7@38.941,40.579 38.941,40.929 39.641,41.629 40.141,41.629 40.391,41.879 R45.2@40.391,42.404 R46.1@41.441,42.404
NetR48_1: R48.1 R49.2 U15.14 | length 3.1
  Top Layer w0.12: R48.1@33.641,40.379 R49.2@33.641,39.379 U15.14@35.741,39.379
NetR50_2: R50.2 U15.4 | length 1.5
  Top Layer w0.12: U15.4@39.641,38.879 R50.2@41.116,38.879
NetR51_1: R51.1 U15.24 | length 3
  Top Layer w0.12: U15.24@38.941,36.679 39.191,36.679 39.891,35.979 39.891,35.229 40.241,34.879 R51.1@40.766,34.879
NetR52_2: R52.2 U17.10 | length 7
  Top Layer w0.5: R52.2@34.191,19.854 34.971,19.854 v1@35,19.825 ; U17.10@38.171,18.284 38.171,17.004 v1@38.175,17
  Signal Layer 2 w0.5: v1@35,19.825 35.6,19.225 35.6,18.225 36.821,17.004 v1(38.166,17.004)
  other v1: 35.016,19.804
NetR53_2: R53.2 U17.15 | length 7.5
  Top Layer w0.5: U17.15@44.521,18.284 44.521,17.029 v1@44.525,17.025 ; v1@47.725,19.825 47.754,19.854 R53.2@48.516,19.854
  Signal Layer 2 w0.5: v1(44.516,17.029) 46.679,17.029 47.125,17.475 47.125,19.3 v1@47.675,19.85
  other v1: 47.716,19.829
NetR60_2: R60.2 SB23.2 | length 75.8
  Top Layer w0.12: v1(23.191,11.479) v1@23.241,11.429
  Top Layer w0.4: v1@23.241,11.429 R60.2@26.266,11.429
  Bottom Layer w0.12: v1(23.191,11.479) 23.435,11.723 23.435,24.43 22.87,24.995 22.87,30.005 22.47,30.405 22.47,30.868 22.635,31.033 22.635,42.805 21.89,43.55 21.89,61.84 27.251,67.201 27.251,69.324 25.975,70.6 25.975,71.591 30.281,75.898 31.973,75.898 32.3,76.225 SB23.2@32.3,76.975
NetR62_2: R62.2 R63.2 T1.1 | length 2.6
  Top Layer w0.5: T1.1@28.291,7.904 28.291,8.654 28.591,8.954 R62.2@28.591,9.454 R63.2@29.491,9.454
NetR73_1: R73.1 SB39.2 SB47.2 | length 64.2
  Top Layer w0.127: v1(38.939,101.967) 38.951,101.979 v1(50.136,101.979)
  Signal Layer 2 w0.127: v1(47.3,63.925) v1(53.9,63.925)
  Bottom Layer w0.12: 50.136,100.9 50.136,96.789 51,95.925 54.05,95.925 54.761,95.214 54.761,90.509 54.17,89.918 54.17,86.169 54.193,86.146 54.193,83.428 54.197,83.425
  Bottom Layer w0.127: SB47.2@46.3,63.675 SB47.2@46.325,63.7 ; SB39.2@46.5,65.075 46.325,64.9 SB47.2@46.325,63.7 ; v1(47.3,63.925) 46.55,63.925 SB47.2@46.325,63.7 ; 50.136,100.9 v1(50.136,101.979) ; v1(53.9,63.925) 53.9,66.252 52.819,67.332 52.819,72.09 54.197,73.467 54.197,83.425
  Bottom Layer w0.3: v1(38.939,101.967) R73.1@39.714,101.967
NetSB13_2: SB13.2 U14.95 | length 5.3
  Top Layer w0.3: U14.95@32.866,82.129 32.866,83.199 34.117,84.45 v1(35.275,84.45)
  Bottom Layer w0.3: v1(35.275,84.45) 36.425,84.45 SB13.2@36.525,84.35
NetSB25_2: SB25.2 U14.121 | length 6.1
  Top Layer w0.12: U14.121@24.291,74.054 25.573,74.054 26.271,74.752 26.271,76.221 v1(27.2,77.15)
  Bottom Layer w0.12: SB25.2@26.25,76.975 26.425,77.15 v1(27.2,77.15)
NetSB56_1: SB56.1 U14.38 | length 6.7
  Top Layer w0.127: v1(44.05,61.9) 44.05,62.05 45.05,63.05 45.05,63.054 U14.38@45.941,63.054
  Bottom Layer w0.127: v1(44.05,61.9) 44.05,61.725 46.025,59.75 SB56.1@46.025,58.5
NetSB74_2: SB74.2 U15.15 | length 2.5
  Top Layer w0.12: v1(34.841,38.879) U15.15@35.741,38.879
  Bottom Layer w0.2: SB74.2@33.291,38.879 v1(34.841,38.879)
NetTP3_1: TP3.1 U13.3 | length 2
  Top Layer w0.3: TP3.1@17.825,92.909 18.895,93.979 U13.3@19.366,93.979
NRST: B2.1 B2.2 C59.2 CN5.12 CN8.5 CN11.14 JP3.2 SB74.1 U14.25 U20.1 U24.5 | length 213.8
  Top Layer w0.12: JP3.2@10.866,99.059 JP3.2@11.156,99.349
  Top Layer w0.2: CN11.14@5.786,86.359 CN8.5@10.866,86.359 ; CN5.12@8.453,116.204 v1(10.441,116.204) ; JP3.2@10.866,99.059 18.176,99.059 18.466,99.349 v1(42.475,99.349) ; v1(38.2,62.075) 38.366,61.909 U14.25@38.366,60.479 38.366,59.472 v1(39.213,58.625) 39.4,58.625 39.825,58.2 C59.2@39.975,58.2 ; U20.1@55.748,8.835 56.135,8.835 56.447,8.523 B2.1@57.653,8.523 v1(60.6,8.523) B2.2@67.153,8.523
  Signal Layer 2 w0.2: v1(31.775,36) v1(31.775,36) 39.301,35.999 39.976,35.324 42.861,35.324 43.08,35.105 45.42,35.105 47.05,33.475 55.2,33.475 56.05,34.325 v1(60.975,34.325)
  Bottom Layer w0.2: U24.5@9.641,116.204 v1(10.441,116.204) 10.441,107.941 8.941,106.441 8.941,100.984 JP3.2@10.866,99.059 9.641,97.834 9.641,87.904 10.866,86.679 CN8.5@10.866,86.359 ; v1(31.775,36) 31.775,38.463 SB74.1@32.191,38.879 32.191,39.666 32.379,39.854 33.879,39.854 35.121,41.096 35.121,48.221 40.45,53.55 40.45,56.304 40.159,56.595 40.155,56.595 39.6,57.15 39.6,58.238 v1(39.213,58.625) ; v1(38.2,62.075) 37.925,62.35 37.925,65.25 36.15,67.025 36.15,79.734 39.875,83.459 39.875,97.172 42.052,99.349 v1(42.475,99.349) ; v1(60.6,8.523) 60.6,30.65 60.975,31.025 v1(60.975,34.325)
OSC32_IN: C71.1 R38.2 X2.2 | length 3.6
  Top Layer w0.12: R38.2@29.225,56.475 29.225,55.825 28.675,55.275 X2.2@28.675,54.9 28.675,54.5 29.275,53.9 C71.1@29.275,53.35
OSC32_OUT: C72.1 R39.2 X2.1 | length 3.6
  Top Layer w0.12: C72.1@30.575,53.35 30.575,53.875 31.175,54.475 X2.1@31.175,54.9 31.175,55.275 30.625,55.825 R39.2@30.625,56.475
OSC_IN: C70.1 SB3.2 X3.1 | length 4.1
  Top Layer w0.12: C70.1@35.55,53.9 X3.1@36.675,53.9 37.17,54.395 37.175,54.395 37.28,54.5 37.28,55.745 SB3.2@36.65,56.375
OSC_OUT: C69.1 SB4.2 X3.3 | length 2.5
  Top Layer w0.12: SB4.2@38.05,56.375 38.05,54.975 38.075,54.95 C69.1@39.15,54.95
PA0: CN11.28 SB58.2 SB75.1 U14.34 | length 81.7
  Top Layer w0.12: U14.34@42.866,60.479 42.866,62.291 v1(43.275,62.7) ; v1(43,44.2) 48.825,44.2 49.25,44.625 49.234,44.625 v1(49.229,44.629)
  Signal Layer 2 w0.12: CN11.28@5.786,68.579 7.104,68.579 9.947,71.422 17.953,71.422 20.452,68.923 23.417,68.923 23.967,69.473 v1(41.5,69.475) v1(41.5,69.475)
  Bottom Layer w0.12: v1(41.5,69.475) 41.5,66.9 43.105,65.295 43.105,62.87 v1(43.275,62.7) 43.275,62.458 42.875,62.058 SB58.2@42.875,58.6 42.875,58.45 43.675,57.65 43.675,56.575 42.025,54.925 42.025,52.075 43,51.1 v1(43,44.2) ; v1(49.229,44.629) 49.532,44.326 49.532,39.243 SB75.1@50.675,38.1
PA1: CN11.30 SB57.1 U14.35 | length 50.3
  Top Layer w0.12: U14.35@43.366,60.479 v1(43.366,61.916)
  Signal Layer 2 w0.12: CN11.30@5.786,66.039 5.786,66.279 9.279,66.279 10.144,67.144 11.324,67.144 11.734,66.734 12.199,66.734 12.849,67.384 17.716,67.384 19.255,65.845 38.241,65.845 38.921,66.525 v1@42.425,66.525 ; 41.33,66.52 v1(42.453,66.52)
  Bottom Layer w0.12: v1(42.453,66.52) 42.453,66.522 42.45,66.525 42.45,66.289 43.345,65.394 43.345,63.21 43.68,62.875 43.68,62.23 v1(43.366,61.916) 43.366,59.759 44.425,58.7 SB57.1@44.425,58.5
PA2: CN12.35 SB72.1 U14.36 | length 44.6
  Top Layer w0.127: U14.36@43.966,60.479 44.646,60.479 v1(44.65,60.475) ; v1@45.7,50.825 45.968,51.093 54.774,51.093 55.886,52.205 65.805,52.205 v1(65.9,52.3)
  Bottom Layer w0.127: v1(44.65,60.475) 45.2,59.925 45.2,55.504 46.277,54.427 46.277,51.923 45.725,51.371 v1(45.725,50.825) SB72.1@45.725,45.1 ; CN12.35@64.206,58.394 64.206,57.71 65.398,56.519 65.398,55.295 65.638,55.055 65.638,52.562 v1(65.9,52.3)
PA3: CN9.1 CN12.37 U14.37 | length 83.8
  Top Layer w0.12: v1(44.7,61.75) 44.7,62.2 44.954,62.454 U14.37@45.941,62.454 ; v1(46.177,50.327) 46.155,50.35 46.155,50.705 46.3,50.85 54.875,50.85 55.987,51.962 65.42,51.962 65.703,51.678 v1(65.703,51.628)
  Signal Layer 2 w0.12: v1(11.975,60.25) 12.405,59.82 14.181,59.82 15.586,61.225 24.625,61.225 25.025,61.625 27.086,61.625 27.701,61.01 43.96,61.01 v1(44.7,61.75)
  Bottom Layer w0.12: CN9.1@10.866,68.579 12.022,68.579 12.301,68.3 12.301,60.576 v1(11.975,60.25) ; v1(44.7,61.75) 46.85,59.6 46.85,56.5 46.52,56.17 46.52,51.822 46.187,51.488 46.187,50.337 v1(46.177,50.327) ; CN12.37@64.206,55.854 65.394,54.666 65.394,52.006 65.703,51.697 v1(65.703,51.628)
PA4: CN7.17 CN11.32 U14.40 | length 83.9
  Top Layer w0.12: v1(44.2,62.85) 44.85,63.5 44.85,63.875 45.029,64.054 U14.40@45.941,64.054
  Signal Layer 2 w0.12: CN11.32@5.786,63.499 4.724,63.499 4.375,63.15 4.375,60.807 5.602,59.58 9.805,59.58 10.079,59.854 11.596,59.854 11.87,59.58 14.28,59.58 15.685,60.985 24.742,60.985 25.082,60.645 44.168,60.645 45.105,61.582 45.105,61.97 44.225,62.85 v1(44.2,62.85) ; v1(41.402,79.504) 41.793,79.895 49.224,79.895 49.649,80.32 56.57,80.32 CN7.17@56.575,80.325
  Bottom Layer w0.12: v1(41.402,79.504) 41.402,79.517 41.405,79.52 41.405,70.145 41.905,69.645 41.905,67.759 42.957,66.707 42.957,66.122 43.6,65.479 43.6,63.45 v1(44.2,62.85)
PA5: CN7.10 CN12.11 SB47.1 U14.41 | length 61.9
  Top Layer w0.12: v1(44.125,63.8) 44.879,64.554 U14.41@45.941,64.554
  Signal Layer 2 w0.12: v1(41.95,94.4) 41.952,94.398 57.044,94.398 57.371,94.725 v1(58.1,94.725) ; CN7.10@59.126,90.423 62.657,90.423 CN12.11@64.206,88.874
  Bottom Layer w0.12: v1(41.95,94.4) 41.955,94.395 41.955,89.332 41.807,89.184 41.807,79.336 41.645,79.174 41.645,70.244 42.145,69.744 42.145,67.859 43.197,66.807 43.197,66.221 43.84,65.578 43.84,64.085 v1(44.125,63.8) 45.1,63.8 SB47.1@45.225,63.675 ; v1(58.1,94.725) 58.1,93.725 57.931,93.556 57.931,91.618 CN7.10@59.126,90.423
PA6: CN7.12 CN12.13 U14.42 | length 44.5
  Top Layer w0.12: U14.42@45.941,65.054 49.517,65.054 v1(49.595,64.976)
  Signal Layer 2 w0.12: v1(49.575,83.275) 54.975,83.275 55.925,84.225 62.097,84.225 CN12.13@64.206,86.334 62.657,87.883 CN7.12@59.126,87.883
  Bottom Layer w0.12: v1(49.575,83.275) 49.575,82.325 49.07,81.82 49.07,81.457 49.76,80.767 49.76,68.437 49.285,67.962 49.285,66.115 49.655,65.745 v1@49.655,64.976
PA7: CN12.15 SB31.1 SB33.2 U14.43 | length 58.1
  Top Layer w0.12: v1(37.65,66.25) 38.346,65.554 U14.43@45.941,65.554 45.945,65.55 v1(49.25,65.55)
  Signal Layer 2 w0.12: v1(33.425,71.275) v1(36.8,71.275) ; v1(48.8,83.25) 48.825,83.25 49.205,82.87 49.743,82.87 49.908,83.035 55.074,83.035 55.947,83.908 64.206,83.908 CN12.15@64.206,83.794
  Bottom Layer w0.12: SB33.2@32.375,69.875 32.275,69.975 SB31.1@32.275,71.275 v1(33.425,71.275) ; v1(36.8,71.275) 36.8,67.1 v1(37.65,66.25) ; v1(48.8,83.25) 48.22,82.67 48.22,81.355 49.52,80.055 49.52,68.536 49.045,68.061 49.045,65.755 v1(49.25,65.55)
PA8: CN12.23 TP4.1 U14.100 | length 66.7
  Top Layer w0.12: U14.100@30.366,82.129 30.366,83.141 31.825,84.6 TP4.1@31.825,84.65 34.985,87.81 38.412,87.81 38.782,88.18 39.14,88.18 39.75,87.57 46.4,87.57 46.495,87.665 46.495,87.668 49.107,90.28 50.537,90.28 50.869,89.948 53.448,89.948 v1(53.825,90.325) ; v1(54.225,93.95) 54.25,93.925 54.633,94.308 62.997,94.308 63.764,95.075 65.85,95.075 v1(65.85,95.1)
  Bottom Layer w0.12: v1(53.825,90.325) 54.521,91.021 54.521,93.654 v1(54.225,93.95) ; CN12.23@64.206,73.634 65.311,74.739 65.311,76.632 65.13,76.813 65.13,77.367 65.401,77.638 65.401,90.526 65.641,90.766 65.641,94.891 v1(65.85,95.1)
PA9: CN12.21 SB23.1 U14.101 | length 41.1
  Top Layer w0.12: U14.101@29.866,82.129 29.866,81.399 30.29,80.975 31.875,80.975 32.25,80.6 v1(32.25,80.575)
  Signal Layer 2 w0.12: v1(32.25,80.575) 32.69,80.135 49.125,80.135 49.55,80.56 55.32,80.56 56.128,81.368 59.584,81.368 60.231,80.721 60.231,80.149 CN12.21@64.206,76.174
  Bottom Layer w0.12: v1(32.25,80.575) 32.3,80.525 SB23.1@32.3,78.075
PA10: CN12.33 SB24.1 U14.102 | length 58.5
  Top Layer w0.12: U14.102@29.366,82.129 29.366,81.384 30.2,80.55 v1(30.95,80.55)
  Signal Layer 2 w0.12: v1(30.95,80.55) 31.38,80.98 32.418,80.98 33.023,80.375 49,80.375 49.425,80.8 55.221,80.8 56.029,81.608 59.683,81.608 60.471,80.82 60.471,80.248 61.465,79.254 v1(61.703,79.254) ; v1(61.578,62.828) 62.312,62.828 CN12.33@64.206,60.934
  Bottom Layer w0.12: SB24.1@30.9,78.075 30.95,78.125 v1(30.95,80.55) ; v1(61.578,62.828) 61.901,63.151 61.901,64.566 61.56,64.907 61.56,67.083 61.901,67.424 61.901,79.025 61.676,79.25 61.699,79.25 v1(61.703,79.254)
PA11: SB16.2 SB21.1 U14.103 | length 3.6
  Top Layer w0.127: U14.103@28.866,82.129 28.866,83.216 28.975,83.325 v1(28.975,83.35)
  Bottom Layer w0.127: v1@28.975,83.325 28.975,82.425 29.3,82.1 ; v1(28.975,83.35) 28.975,84.125 29.125,84.275
PA12: SB17.2 SB22.1 U14.104 | length 3.8
  Top Layer w0.127: v1(28.25,83.35) 28.25,83.3 28.366,83.184 U14.104@28.366,82.129
  Bottom Layer w0.127: SB22.1@27.766,82.229 27.766,82.316 28.2,82.75 28.2,83.375 v1@28.225,83.35 ; SB17.2@27.775,84.35 28.15,83.975 28.15,83.45 v1(28.25,83.35)
PA13: CN5.4 CN11.13 R10.1 U8.5 U14.105 | length 77.4
  Top Layer w0.12: CN11.13@3.246,86.359 4.594,87.707 10.887,87.707 10.89,87.711 11.426,87.711 11.673,87.464 14.35,87.464 15.57,86.244 25.118,86.244 25.73,86.855 26.32,86.855 27.845,85.33 27.845,82.15 U14.105@27.866,82.129 ; v1(6.466,120.729) 6.816,120.729 7.371,121.284 CN5.4@8.453,121.284 10.861,121.284 10.861,121.424 11.291,121.854 14.541,121.854 15.091,121.304 U8.5@15.466,121.304
  Bottom Layer w0.12: CN11.13@3.246,86.359 1.286,88.319 1.286,113.424 6.991,119.129 6.991,120.204 v1(6.466,120.729)
PA14: CN5.6 CN11.15 R11.2 U8.4 U14.109 | length 72.2
  Top Layer w0.12: CN11.15@3.246,83.819 4.351,82.714 6.244,82.714 6.669,83.139 9.983,83.139 10.408,82.714 20.086,82.714 22.646,80.154 U14.109@24.291,80.154 ; v1(6.401,120.014) CN5.6@8.453,120.014 10.856,120.014 R11.2@10.866,120.004 11.491,119.379 12.091,119.379 12.521,118.949 14.011,118.949 15.066,120.004 U8.4@15.466,120.004
  Bottom Layer w0.12: CN11.15@3.246,83.819 1.046,86.019 1.046,113.848 6.401,119.203 v1(6.401,120.014)
PA15: CN5.10 CN7.9 CN11.17 U8.1 U14.110 | length 141.9
  Top Layer w0.12: CN11.17@3.246,81.279 4.441,82.474 6.483,82.474 6.909,82.899 9.101,82.899 v1(9.526,82.474) 19.987,82.474 22.907,79.554 U14.110@24.291,79.554 ; CN5.10@8.453,117.474 v1(10.3,117.474) 13.336,117.474 14.366,118.504 v1(14.841,118.504) ; v1(9.5,107.95) 9.8,108.25 25.325,108.25 25.9,107.675 32.375,107.675 35.55,110.85 56.3,110.85 v1(56.4,110.75) ; U8.1@13.766,121.304 14.216,121.304 14.841,120.679 v1(14.916,120.679)
  Bottom Layer w0.12: v1(9.526,82.474) 9.161,82.839 9.161,84.867 9.618,85.324 9.618,87.508 8.736,88.39 8.736,99.864 8.375,100.225 8.375,106.825 v1(9.5,107.95) 10.061,108.511 10.061,115.164 9.875,115.35 9.275,115.35 8.9,115.725 8.9,116.925 9.449,117.474 v1(10.3,117.474) ; v1(14.841,118.504) 14.841,120.604 v1(14.916,120.679) ; v1(56.4,110.75) 56.4,109.839 56.496,109.743 56.496,103.204 57.691,102.009 57.691,91.528 CN7.9@56.586,90.423
PB0: CN10.31 CN11.34 SB39.1 U14.46 | length 92.7
  Top Layer w0.12: CN11.34@5.786,60.959 8.284,60.959 9.479,62.154 16,62.154 16.529,61.625 v1(16.529,61.646) ; v1(43.55,68.075) 44.375,67.25 44.8,67.25 44.996,67.054 U14.46@45.941,67.054 ; v1(47.45,35.575) 47.45,35.55 47.452,35.552 56.579,35.552 CN10.31@56.586,35.559
  Signal Layer 2 w0.12: v1(16.529,61.646) 24.707,61.646 24.926,61.865 27.185,61.865 27.8,61.25 42.173,61.25 42.78,61.857 42.78,62.198 42.775,62.203 42.775,63.05 v1(44.3,64.575) 47.85,61.025 48.612,61.025 48.987,61.4 v1(49.725,61.4)
  Bottom Layer w0.12: v1(43.55,68.075) 43.55,66.208 44.5,65.258 44.5,65.075 ; v1(44.3,64.575) 44.3,64.875 44.5,65.075 ; SB39.1@45.4,65.075 44.5,65.075 ; v1(47.45,35.575) 47.755,35.88 47.755,41.99 47.482,42.262 47.482,43.6 48.385,44.502 48.385,51.642 49.202,52.459 49.202,54.923 49.31,55.031 49.31,56.396 49.67,56.756 49.67,56.76 49.91,57 49.91,61.19 49.725,61.375 v1(49.725,61.4)
PB1: CN9.7 CN12.24 U14.47 | length 73.1
  Top Layer w0.12: v1(44.602,67.927) 44.975,67.554 U14.47@45.941,67.554 48.783,67.554 49.789,68.56 53.473,68.56 54.649,67.384 57.143,67.384 57.658,66.869 58.054,66.869 58.569,67.384 65.509,67.384 65.7,67.575 v1(65.725,67.575)
  Signal Layer 2 w0.12: v1(11.875,67.225) 11.9,67.225 11.975,67.3 11.975,68.711 12.948,69.684 14.031,69.684 16.091,67.624 17.816,67.624 18.814,66.625 21.427,66.625 22.307,67.505 22.82,67.505 23.435,66.89 29.367,66.89 30.132,67.655 44.425,67.655 44.602,67.832 v1(44.602,67.927)
  Bottom Layer w0.12: CN9.7@10.866,60.959 10.87,60.959 12.061,62.15 12.061,67.039 v1(11.875,67.225) ; v1(65.725,67.575) 65.551,67.749 65.551,72.439 CN12.24@66.746,73.634
PB2: CN12.22 SB63.1 SB69.1 U14.48 | length 83.3
  Top Layer w0.12: v1(18.85,52.55) 25.337,52.55 27.099,50.788 44.725,50.788 46.677,52.74 47.884,52.74 v1(48.049,52.905) ; U14.48@45.941,68.054 47.25,68.054 ; 47.25,68.05 v1(47.8,68.05) 48.939,68.05 49.689,68.8 53.806,68.8 v1(54.578,68.028) ; v1(48.675,58.3) 49.7,57.275 51.4,57.275 51.428,57.247 v1(51.428,57.203) ; v1(54.83,71.675) 55.252,71.675 55.8,72.224 67.249,72.224 67.554,72.529 v1(67.578,72.529)
  Signal Layer 1 w0.12: v1@51.425,57.205 v1(51.428,57.203)
  Signal Layer 2 w0.12: CN12.22@66.746,76.174 67.851,75.069 67.851,72.758 67.621,72.529 v1(67.578,72.529)
  Bottom Layer w0.12: v1(18.85,52.55) SB69.1@18.85,53.3 ; v1(47.8,68.05) 47.725,68.05 47.74,68.035 47.74,66.473 48.013,66.2 48.013,64.754 48.39,64.377 48.39,62.315 47.795,61.72 47.795,61.357 48.675,60.477 v1(48.675,58.3) 48.14,57.765 48.14,56.202 47.78,55.842 47.78,55.308 48.049,55.039 v1(48.049,52.905) ; SB63.1@50.675,56.375 50.675,56.95 50.928,57.203 v1(51.428,57.203) ; v1(54.578,68.028) 54.578,69.151 54.995,69.569 54.995,71.51 v1(54.83,71.675)
PB3: CN12.31 SB26.1 SB32.2 U14.133 | length 62.6
  Top Layer w0.12: v1(22.85,67.975) 22.929,68.054 U14.133@24.291,68.054 ; v1(61.428,69.203) v1@61.428,69.222
  Signal Layer 2 w0.12: v1(22.025,71.1) 22.97,72.045 22.97,73.28 24.564,74.875 29.45,74.875 v1(30,74.325) 30.55,74.875 57.57,74.875 58.021,74.424 58.021,73.201 58.668,72.554 60.671,72.554 61.428,71.797 v1(61.428,69.203) ; v1(61.253,64.278) 61.322,64.278 62.126,63.474 CN12.31@64.206,63.474
  Bottom Layer w0.12: 21.225,71.3 21.825,71.3 v1(22.025,71.1) 22.079,71.046 22.079,68.821 22.85,68.05 v1(22.85,67.975) ; v1(30,74.325) SB26.1@31.275,74.325 ; v1(61.253,64.278) 61.08,64.451 61.08,67.334 61.421,67.675 61.421,68.002 61.045,68.378 61.045,68.718 61.428,69.101 v1(61.428,69.203)
PB4: CN7.19 CN12.27 U14.134 | length 61.5
  Top Layer w0.12: U14.134@24.291,67.554 28.879,67.554 30.15,68.825 v1(32.975,68.825) ; CN7.19@56.586,77.723 57.348,77.723 58.543,78.918 60.857,78.918 v1(61.475,78.3) ; v1(61,67.85) 61.226,67.624 63.276,67.624 CN12.27@64.206,68.554
  Signal Layer 2 w0.12: v1(34.227,77.723) 34.245,77.705 56.568,77.705 CN7.19@56.586,77.723
  Bottom Layer w0.12: v1(32.975,68.825) 33,68.825 33.275,69.1 33.275,70.4 34.227,71.352 v1(34.227,77.723) ; v1(61,67.85) 60.805,68.045 60.805,69.153 61.661,70.009 61.661,78.1 61.4,78.361 61.4,78.375 v1(61.475,78.3)
PB5: CN7.13 CN12.29 SB35.2 U14.135 | length 65.4
  Top Layer w0.12: U14.135@24.291,67.054 30.121,67.054 30.125,67.05 v1(30.125,67.075)
  Signal Layer 2 w0.12: v1(30.125,67.075) 30.465,67.415 47.743,67.415 49.201,68.873 54.729,68.873 56.187,67.415 57.685,67.415 v1(57.8,67.3) 57.915,67.415 59.652,67.415 60.327,66.74 62.592,66.74 62.757,66.905 63.093,66.905 63.984,66.014 CN12.29@64.206,66.014
  Bottom Layer w0.12: v1(30.125,67.075) 30.175,67.125 SB35.2@30.175,68.475 ; CN7.13@56.586,85.343 56.963,85.343 57.691,84.615 57.691,79.25 57.695,79.246 57.695,78.99 57.691,78.986 57.691,70.516 56.859,69.684 56.128,69.684 55.481,69.037 55.481,68.121 56.128,67.474 57.626,67.474 v1(57.8,67.3)
PB6: CN12.17 SB8.2 SB9.2 SB61.1 U14.136 | length 103.1
  Top Layer w0.12: v1(22.475,67.1) 23.021,66.554 U14.136@24.291,66.554 ; v1(49.702,89.379) 49.716,89.393 50.406,89.393 50.571,89.228 62.922,89.228 v1(62.925,89.225) ; v1(52.35,59.275) 52.904,59.829 61.879,59.829 v1(62.6,60.55)
  Signal Layer 2 w0.12: v1(22.475,67.1) 22.475,67.075 22.9,66.65 30.35,66.65 30.875,67.175 47.842,67.175 49.301,68.633 54.629,68.633 56.088,67.175 57.013,67.175 57.559,66.629 58.153,66.629 58.699,67.175 59.553,67.175 60.228,66.5 v1(62.925,66.5)
  Bottom Layer w0.12: SB9.2@47.875,88.35 SB8.2@49.275,88.35 49.725,88.8 49.725,89.357 v1(49.702,89.379) ; SB61.1@51.575,58.725 SB61.1@51.575,58.7 52.125,58.7 52.35,58.925 v1(52.35,59.275) ; v1(62.6,60.55) 62.202,60.948 62.202,61.46 62.207,61.466 62.207,61.493 63.101,62.387 63.101,66.324 v1(62.925,66.5) 63.101,66.676 63.101,80.149 CN12.17@64.206,81.254 63.101,82.359 63.101,89.049 v1(62.925,89.225)
PB7: CN11.21 SB34.2 SB68.1 U14.137 | length 99.2
  Top Layer w0.12: v1(6.7,70.225) 7.1,70.225 8.4,71.525 17.575,71.525 21.075,68.025 v1@22.1,68.025 ; v1(6.991,51.429) 7.187,51.232 8.832,51.232 9.834,52.234 11.632,52.234 11.962,51.904 25.507,51.904 26.862,50.548 44.825,50.548 46.776,52.5 48.25,52.5 48.7,52.95 48.7,54.125 49.125,54.55 v1(49.875,54.55) ; v1(22.175,68.025) v1@22.1,68.025 ; U14.137@24.291,66.054 22.848,66.054 22.07,66.832 22.07,67.995 v1@22.1,68.025
  Bottom Layer w0.12: CN11.21@3.246,76.199 3.246,75.92 4.402,74.764 6.244,74.764 6.891,74.117 6.891,70.416 v1(6.7,70.225) 6.891,70.034 6.891,66.497 7.636,65.752 7.636,58.261 7.371,57.996 7.371,56.171 6.891,55.691 6.891,51.528 v1(6.991,51.429) ; SB34.2@21,69.075 21,68.45 21.425,68.025 v1(22.175,68.025) ; v1(49.875,54.55) 49.875,55 50.15,55.275 SB68.1@50.675,55.275
PB8: CN7.2 CN12.3 SB62.1 U14.139 | length 88
  Top Layer w0.12: v1(17.325,66.5) 21.511,66.5 22.957,65.054 U14.139@24.291,65.054 25.879,65.054 27.495,66.67 31.17,66.67 v1(31.225,66.725) ; v1(37.475,88.9) 39.438,88.9 39.763,88.575 v1(41.1,88.575) ; v1(43.4,99.35) 43.528,99.478 58.021,99.478 CN7.2@59.126,100.583 61.212,100.583 62.761,99.034 CN12.3@64.206,99.034
  Bottom Layer w0.12: v1(17.325,66.5) 17.195,66.37 17.195,63.374 15.845,62.024 15.845,60.38 16.175,60.05 18.675,60.05 18.85,59.875 SB62.1@18.85,59.35 ; v1(31.225,66.725) 31.5,66.725 33.515,68.74 33.515,70.301 34.632,71.418 34.632,79.882 37.475,82.725 v1(37.475,88.9) ; v1(41.1,88.575) 41.125,88.6 41.125,97.075 v1(43.4,99.35)
PB9: CN7.4 CN12.5 SB55.1 U14.140 | length 81.6
  Top Layer w0.12: v1(17.775,66.025) 17.775,66.05 17.985,66.26 21.411,66.26 23.118,64.554 U14.140@24.291,64.554 26.004,64.554 27.775,66.325 31.052,66.325 31.057,66.32 31.795,66.32 v1(31.8,66.325) ; v1(37.875,89.5) v1(41.55,89.5) ; v1(43.45,98.7) 43.988,99.238 57.931,99.238 CN7.4@59.126,98.043
  Top Layer w0.127: CN7.4@59.126,98.043 60.952,98.043 62.501,96.494 CN12.5@64.206,96.494
  Bottom Layer w0.12: v1(17.775,66.025) 17.775,65.248 17.595,65.068 17.595,64.655 17.775,64.475 17.775,62.225 SB55.1@17.95,62.05 ; v1(31.8,66.325) 31.8,66.686 33.755,68.641 33.755,70.201 34.872,71.318 34.872,79.783 37.715,82.626 37.715,88.567 37.88,88.732 37.88,89.211 37.875,89.216 v1(37.875,89.5) ; v1(41.55,89.5) 41.365,89.685 41.365,96.976 43.089,98.7 v1(43.45,98.7)
PB10: CN10.32 CN12.25 U14.69 | length 75.1
  Top Layer w0.12: U14.69@45.941,78.554 47.071,78.554 48.135,77.49 54.99,77.49 55.275,77.775 v1(55.275,78.554) ; 55.796,34.454 58.021,34.454 CN10.32@59.126,35.559
  Signal Layer 2 w0.12: v1(55.275,78.554) 55.515,78.554 56.029,79.068 57.143,79.068 57.458,78.753 58.268,78.753 58.343,78.828 59.584,78.828 60.595,77.817 60.595,76.732 60.832,76.495 61.905,76.495 63.101,75.299 63.101,72.199 CN12.25@64.206,71.094
  Bottom Layer w0.12: v1(55.275,78.554) 54.68,77.959 54.68,73.267 54.185,72.772 54.185,70.852 54.515,70.522 54.515,69.768 53.91,69.162 53.91,67.784 55.001,66.693 55.001,51.795 54.761,51.555 54.761,49.971 54.945,49.787 54.945,38.932 55.185,38.692 55.185,36.567 55.481,36.271 55.481,34.769 v1(55.625,34.625)
PB11: CN10.34 CN12.18 U14.70 | length 74.9
  Top Layer w0.12: U14.70@45.941,79.054 46.971,79.054 48.25,77.775 54.475,77.775 54.87,78.17 54.87,78.746 v1(55.328,79.204) 55.482,79.05 58.336,79.05 58.443,79.158 60.808,79.158 61.469,79.819 65.311,79.819 CN12.18@66.746,81.254 ; v1(55.075,34) 55.15,34 55.364,34.214 57.931,34.214 CN10.34@59.126,33.019
  Bottom Layer w0.12: v1(55.075,34) 55.22,34.145 55.22,36.193 54.945,36.468 54.945,38.593 54.705,38.833 54.705,49.687 54.521,49.871 54.521,51.654 54.761,51.894 54.761,66.593 53.67,67.685 53.67,69.262 54.275,69.867 54.275,70.423 53.945,70.753 53.945,72.872 54.44,73.367 54.44,78.315 v1@55.328,79.203
PB12: CN7.7 CN12.16 U14.73 | length 47.3
  Top Layer w0.12: U14.73@43.966,82.129 43.966,82.741 44.95,83.725 55.945,83.725 56.128,83.908 62.757,83.908 63.748,84.899 64.664,84.899 65.769,83.794 CN12.16@66.746,83.794 ; CN7.7@56.586,92.963 57.691,94.068 59.707,94.068 60.926,92.849 67.474,92.849 67.925,93.3 v1(67.925,93.325)
  Bottom Layer w0.12: CN12.16@66.746,83.794 66.746,84.671 67.925,85.85 v1(67.925,93.325)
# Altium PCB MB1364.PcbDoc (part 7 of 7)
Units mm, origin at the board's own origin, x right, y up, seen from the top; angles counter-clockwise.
Board outline 70 x 133.34 mm, 6 copper layers (Top Layer, Signal Layer 1, Signal Layer 2, Signal Layer 3, Signal Layer 4, Bottom Layer), stack 1.57 mm thick; 320 components, 286 nets, 1370 pads, 2009 vias.

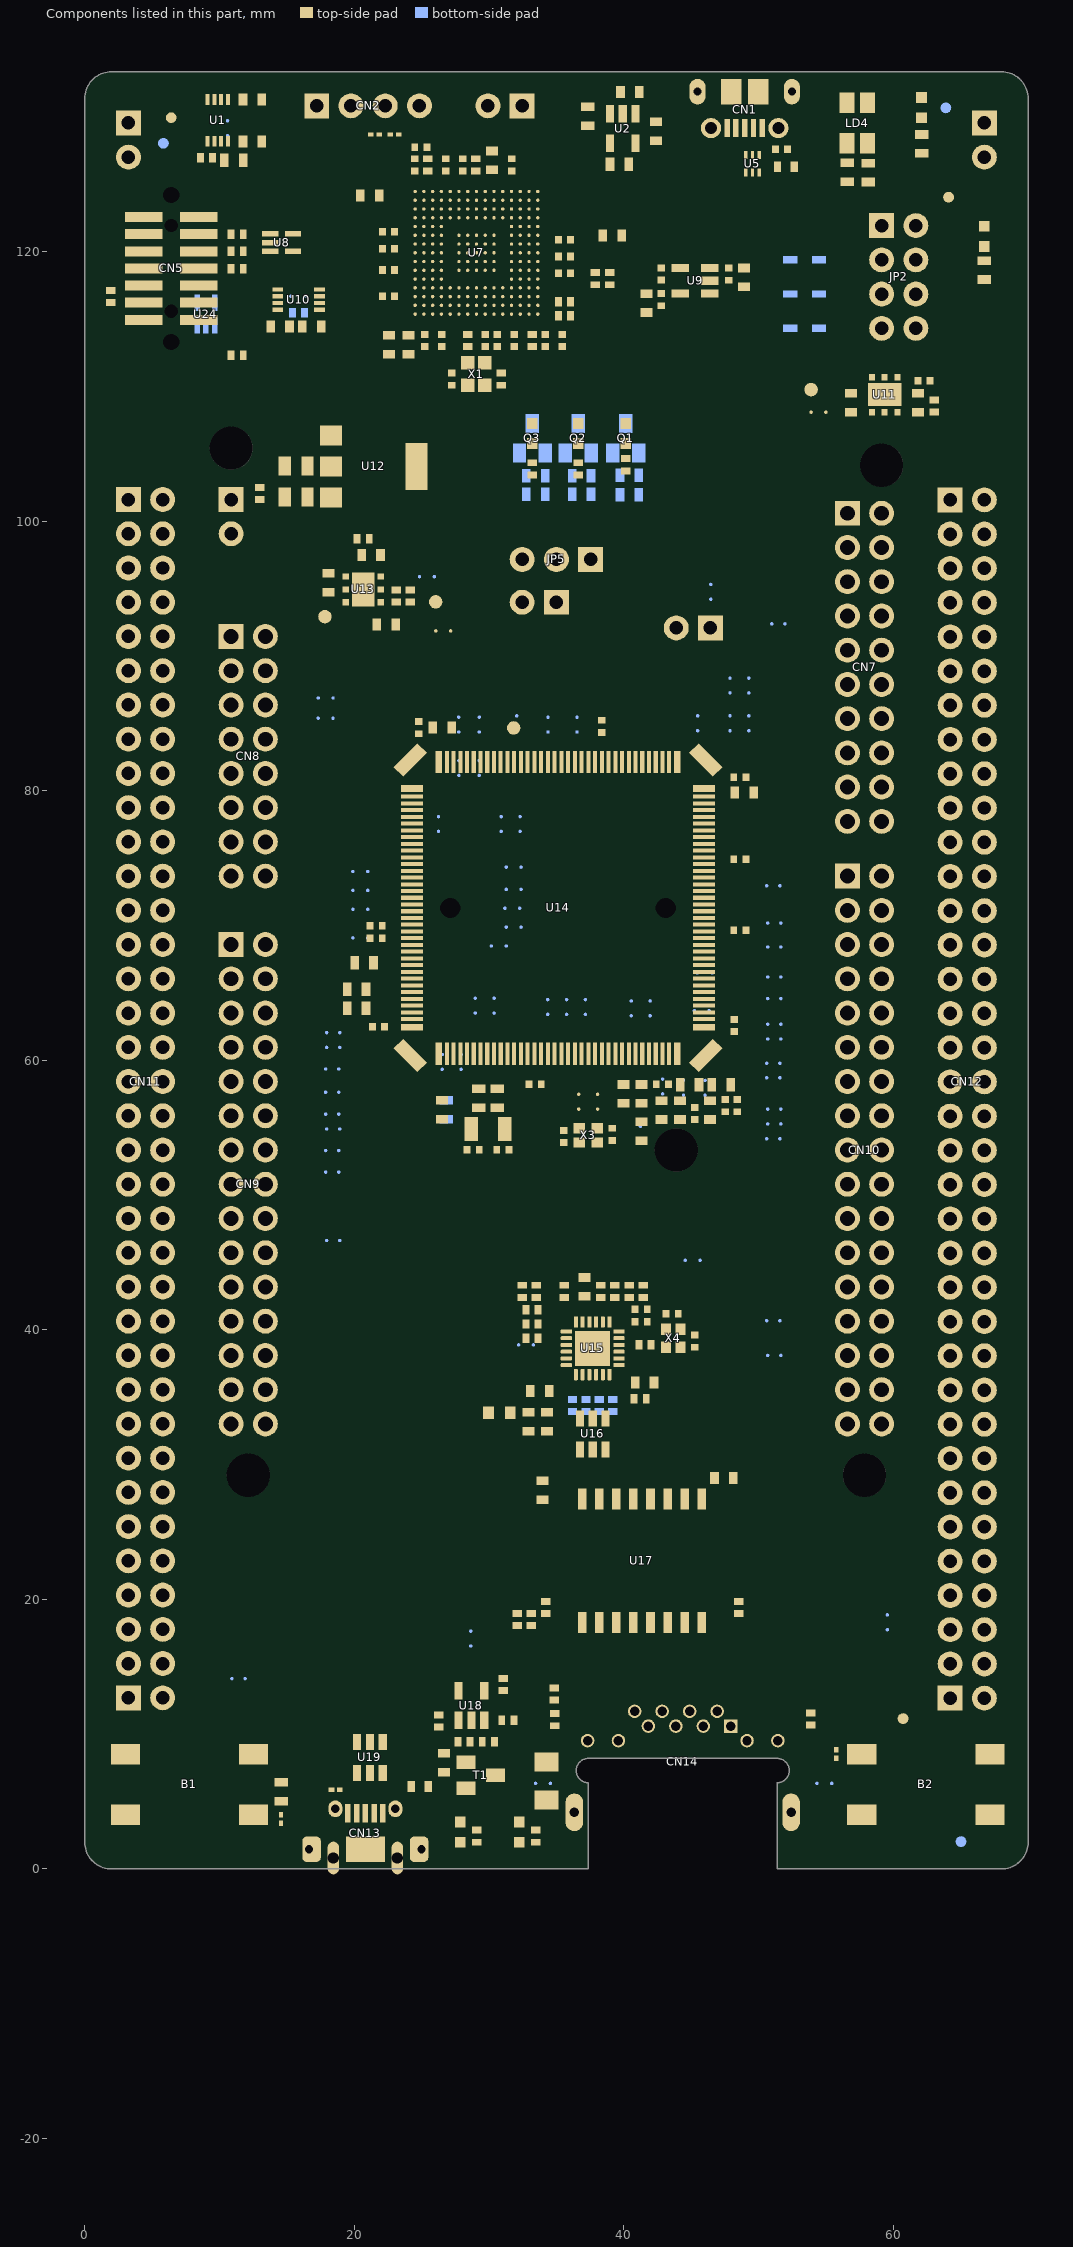
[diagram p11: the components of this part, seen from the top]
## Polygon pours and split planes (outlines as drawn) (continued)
VIN on Top Layer "VIN_L01_P026" (solid, remove dead copper, pour order 26): 16.041,102.829 15.816,102.604 15.816,100.504 16.041,100.279 19.816,100.279 20.016,100.479 20.016,102.604 19.791,102.829
GND on Top Layer "GND_L01_P114" (solid, remove dead copper, pour order 114): 1.574,133.34 0.112,131.879 0.112,107.629 20.162,107.629 20.662,108.129 25.862,108.129 26.612,107.379 26.612,100.379 25.987,99.754 16.287,99.754 15.412,100.629 13.862,100.629 13.862,107.629 0.112,107.629 0.112,1.629 1.612,0.129 35.362,0.129 35.362,12.379 28.987,12.379 28.612,12.004 28.612,8.979 27.012,7.379 26.262,7.379 25.362,6.479 25.362,4.379 23.862,2.879 21.862,2.879 21.362,3.379 21.362,5.379 25.112,9.129 25.112,14.629 25.362,14.879 35.862,14.879 35.862,8.379 53.362,8.379 53.365,0 68.233,0 69.862,1.629 69.862,106.879 60.112,106.879 59.612,107.379 59.612,108.629 59.862,108.879 63.112,108.879 63.112,111.879 62.612,112.379 60.646,112.379 59.862,113.163 59.862,124.137 60.604,124.879 63.612,124.879 64.362,124.129 64.362,119.379 64.862,118.879 67.392,118.879 67.392,118.849 67.862,118.379 67.862,107.629 67.612,107.379 67.612,107.129 69.862,107.129 69.862,131.879 68.401,133.34
GND on Signal Layer 2 "GND_L03_P098" (solid, remove dead copper, pour order 98): 0.566,10.029 1.616,8.979 15.041,8.979 18.116,12.054 27.141,12.054 27.666,12.579 34.091,12.579 34.416,12.904 34.416,13.054 35.291,13.929 69.891,13.929 69.941,13.879 69.941,1.204 68.816,0.079 1.216,0.079 0.216,1.079 0.216,10.004 0.191,10.029
GND on Signal Layer 2 "GND_L03_P096" (solid, remove dead copper, pour order 96): 26.666,100.8 26.766,100.9 34.4,100.9 44.6,90.7 44.6,82.003 69.494,82 69.605,81.914 69.941,81.577 69.941,12.204 69.916,12.179 27.616,12.179 27.616,14.229 27.316,14.529 15.691,14.529 13.166,12.004 1.316,12.004 0.579,11.266 0.253,11.266 0.116,11.404 0.116,104.829 0.216,104.929 7.491,104.929 8.751,103.669 10.4,103.669 10.4,101.945 12.241,100.104 25.916,100.104 26.666,100.854
GND on Signal Layer 2 "GND_L03_P094" (solid, remove dead copper, pour order 94): 0.091,113.329 0.391,113.329 1.491,112.229 4.166,112.229 5.641,113.704 38.666,113.704 45.116,120.154 58.621,120.154 59.825,118.95 59.825,113.6 60.475,112.95 69.471,112.95 69.866,112.555 69.866,81.879 43.116,81.879 42.366,82.629 42.366,83.559 42.366,85.429 41.766,86.029 31.966,86.029 27.225,90.77 27.225,106.795 25.716,108.304 20.491,108.304 19.891,107.704 19.891,105.829 18.466,104.404 11.741,104.404 10.716,103.379 10.716,100.529 10.566,100.379 0.341,100.379 0.091,100.629
GND on Signal Layer 2 "GND_L03_P092" (solid, remove dead copper, pour order 92): 2,133.34 1.986,133.354 1.55,133.354 -0.009,131.795 -0.009,117.504 0.166,117.329 0.916,117.329 4.391,120.804 23.941,120.804 26.391,118.354 35.841,118.354 41.566,124.079 48.041,124.079 50.816,126.854 63.146,126.854 68,122 68,114.025 66.054,112.079 69.816,112.079 69.816,132.004 68.491,133.329
VIN on Signal Layer 2 "VIN_L03_P082" (solid, remove dead copper, pour order 82): 12.441,104.079 12.016,104.079 11.191,103.254 11.191,101.679 12.566,100.304 19.716,100.304 19.991,100.579 19.991,102.279 19.366,102.904 18.196,104.074 17.341,104.074
5V on Signal Layer 2 "5V_L03_P062" (solid, remove dead copper, pour order 62): 15.866,14.304 13.316,11.754 1.441,11.754 1.091,11.404 1.091,9.979 1.716,9.354 14.791,9.354 17.816,12.379 27.091,12.379 27.366,12.654 27.366,14.079 27.141,14.304
5V on Signal Layer 2 "5V_L03_P060" (solid, remove dead copper, pour order 60): 60.527,113.837 60.99,113.3 66.8,113.3 67.525,114.025 67.525,121.75 62.871,126.404 50.866,126.404 48.191,123.729 41.841,123.729 36.066,117.954 26.266,117.954 23.766,120.454 4.541,120.454 1.091,117.004 1.091,113.079 1.691,112.479 3.941,112.479 5.466,114.004 38.241,114.004 44.791,120.554 59.971,120.554 60.527,119.998
5V_VIN on Signal Layer 2 "5V_VIN_L03_P034" (solid, remove dead copper, pour order 34): 19.366,104.779 20.316,105.729 20.316,107.504 20.666,107.854 25.641,107.854 26.016,107.479 26.016,100.629 25.666,100.279 20.491,100.279 20.291,100.479 20.291,102.429 19.591,103.129 19.366,103.354
GND on Signal Layer 1 "GND_L02_P020" (solid, remove dead copper, pour order 20): 35.266,0 35.266,11.429 37.241,13.404 51.516,13.404 53.666,11.254 53.666,8.429 53.491,8.254 53.491,0 69.037,0 69.416,0.379 70,0.963 70,132.345 69.005,133.34 68,133.34 -0.034,133.379 -0.034,0.929 0.895,0
GND on Signal Layer 4 "GND_L05_P050" (solid, remove dead copper, pour order 50): 35.369,0.079 35.369,11.606 37.766,14.004 49.991,14.004 53.541,10.454 53.541,0.054 53.591,0.079 68.541,0.079 69.866,1.404 69.866,131.829 68.466,133.229 1.791,133.254 1.516,133.254 0.041,131.779 0.041,1.629 1.591,0.079

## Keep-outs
Bottom Layer:
  lines w0.01: 57.551,67.287 ccw(c56.608,71.097) 57.756,67.344 ; 60.327,67.271 cw(c56.608,66.017) 60.36,67.169
Keep-Out Layer:
  lines w0.127: -0.004,1.999 ccw(c1.996,1.999) 1.996,-0.001

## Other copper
Top Layer:
  pour cut-out: 35.366,17.35 53.366,17.35 53.366,-0.121 35.366,-0.121
  pour cut-out: 29.6,20.55 36.366,20.55 36.366,0 29.6,0
  pour cut-out: 48.616,126.679 48.616,126.254 49.966,126.254 49.966,126.734 48.621,126.734 48.616,126.729
  pour cut-out: 35.366,-0.121 35.366,12.879 35.866,13.379 52.866,13.379 53.366,12.879 53.366,-0.121
  pour cut-out: 24.316,126.629 23.271,126.629 21.721,125.079 21.721,122.206 21.536,122.021 21.536,113.804 22.001,113.339 26.226,113.339 26.891,114.004 26.891,115.779 27.446,116.334 28.79,116.334 29.716,115.408 29.716,113.904 30.416,113.204 35.791,113.204 36.291,113.704 36.291,121.204 36.116,121.379 31.791,121.379 31.791,122.379 32.49,123.078 32.49,126.627
  text "1" at 67.368,104.084 h2 r90
Signal Layer 1:
  pour cut-out: 29.6,20.55 36.366,20.55 36.366,0 29.6,0
  pour cut-out: 35.366,17.35 53.366,17.35 53.366,-0.121 35.366,-0.121
  text "2" at 67.368,105.334 h2 r90
Signal Layer 2:
  pour cut-out: 35.366,17.35 53.366,17.35 53.366,-0.121 35.366,-0.121
  pour cut-out: 30.125,21.275 36.366,21.275 36.366,0 30.125,0
  pour cut-out: 35.366,-0.121 35.366,12.879 35.866,13.379 52.866,13.379 53.366,12.879 53.366,-0.121
  text "3" at 67.368,106.834 h2 r90
Signal Layer 3:
  pour cut-out: 35.325,17.421 53.325,17.421 53.325,-0.05 35.325,-0.05
  pour cut-out: 35.366,-0.121 35.366,12.879 35.866,13.379 52.866,13.379 53.366,12.879 53.366,-0.121
  text "4" at 67.368,109.084 h2 r90
Signal Layer 4:
  pour cut-out: 52.225,8.2 56.291,8.2 56.291,0 52.225,0
  pour cut-out: 35.366,17.35 53.366,17.35 53.366,-0.121 35.366,-0.121
  pour cut-out: 32.3,8.2 36.366,8.2 36.366,0 32.3,0
  text "5" at 67.368,110.584 h2 r90
Bottom Layer:
  pour cut-out: 56.459,0 53.525,0 53.525,20.225 56.459,20.225
  pour cut-out: 32.541,19.7 35.475,19.7 35.475,0 32.541,0
  pour cut-out: 32.575,17.366 32.575,20.3 56.325,20.3 56.325,17.366
  text "6" at 67.368,112.084 h2 r90
Multi-Layer:
  pour cut-out: 36.441,28.359 36.441,17.359 46.266,17.359 46.266,28.359
  pour cut-out: 65.75,103.85 67.75,103.85 67.75,112.35 65.75,112.35

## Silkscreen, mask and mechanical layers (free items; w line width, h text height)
Top Overlay:
  drawing of 331 lines, arcs and shapes, not listed
  text "OVCR" at 60.186,132.098 h1.5
  text "COM" at 55.903,132.049 h1.5
  text "SWD" at 27.254,129.311 h1.5 r90
  text "STLK_RST" at 29.705,128.396 h0.91
  text "3V3" at 15.966,128.329 h1.5
  text "USB" at 45.027,127.236 h1.5
  text "STLK" at 15.394,127.064 h1.5
  text "GND" at 69.125,126.8 h1.5 r90
  text "GND" at 1.825,126.775 h1.5 r90
  text "PWR" at 44.861,126.086 h1.5
  text "ST-LINK V3" at 34.621,122.81 h1.5
  text "STLINK" at 52.72,121.407 h1.5
  text "VIN" at 55.15,118.795 h1.5
  text "5V" at 63.2,118.3 h1.5
  text "PWR" at 63.125,116.7 h1.5
  text "EXT" at 54.852,116.332 h1.5
  text "RX" at 0.706,114.299 h1.5
  text "TX" at 10.391,114.299 h1.5
  text "CHGR" at 53.48,113.769 h1.5
  text "MIPI10" at 4.326,111.224 h1.5
  text "3V3" at 52.749,110.764 h1.5
  text "5V_VIN" at 25.824,103.769 h1.5
  text "SCL" at 60.916,101.154 h1.2 r45
  text "User LEDs" at 34.039,101.13 h1.5
  text "D15" at 60.991,100.029 h1.2 r45
  text "VIN" at 17.315,99.842 h1.5
  text "E" at 43.625,99.425 h15
  text "1V8-VDD-3V3" at 30.831,98.704 h1.5
  text "SDA" at 60.916,98.379 h1.2 r45
  text "D14" at 60.991,97.229 h1.2 r45
  text "MCU_RST" at 7.776,96.466 h1.5
  text "+" at 62.291,95.379 h1.2 r45
  text "VREF" at 60.966,95.204 h1.2 r45
  text "I2S_A" at 54.017,94.409 h1.5 r90
  text "IDD" at 37.35,93.425 h1.5
  text "GND" at 60.891,92.779 h1.2 r45
  text "NC" at 7.741,92.154 h1.2 r315
  text "VDD_MCU" at 30.45,91.475 h1.5
  text "SCK" at 60.916,90.904 h1.2 r45
  text "D13" at 61.016,89.779 h1.2 r45
  text "IO" at 8.216,89.754 h1.2 r315
  text "RMII TXD1" at 41.862,89.533 h1.5
  text "REF" at 7.491,89.004 h1.2 r315
  text "MISO" at 60.966,88.079 h1.2 r45
  text "NRST" at 7.116,86.904 h1.2 r315
  text "D12" at 61.016,86.879 h1.2 r45
  text "I2S_B" at 54.719,85.921 h1.5 r90
  text "MOSI" at 60.991,85.329 h1.2 r45
  text "D11" at 60.966,84.079 h1.2 r45
  text "3V3" at 7.716,83.904 h1.2 r315
  text "SDMMC" at 16.676,82.753 h1.5 r90
  text "CS" at 60.891,82.629 h1.2 r45
  text "D10" at 60.966,81.479 h1.2 r45
  text "5V" at 7.841,81.354 h1.2 r315
  text "PWM" at 60.991,80.104 h1.2 r45
  text "GND" at 7.441,79.054 h1.2 r315
  text "D9" at 61.016,78.904 h1.2 r45
  text "SPI_B" at 54.151,78.837 h1.5 r90
  text "I/O" at 61.016,77.429 h1.2 r45
  text "GND" at 7.416,76.479 h1.2 r315
  text "D8" at 61.016,76.229 h1.2 r45
  text "IO" at 16.64,74.292 h1.5 r90
  text "I/O" at 61.041,74.204 h1.2 r45
  text "VIN" at 7.466,73.879 h1.2 r315
  text "AVDD" at 51.445,73.179 h1.5
  text "D7" at 61.041,72.954 h1.2 r45
  text "PWM" at 61.016,71.554 h1.2 r45
  text "AGND" at 51.342,70.602 h1.5
  text "D6" at 61.041,70.404 h1.2 r45
  text "A0" at 7.758,69.168 h1.2 r315
  text "PWM" at 61.041,69.029 h1.2 r45
  text "GND" at 52.309,68.223 h1.5
  text "D5" at 61.041,67.854 h1.2 r45
  text "A1" at 7.841,66.679 h1.2 r315
  text "I/O" at 61.016,66.429 h1.2 r45
  text "D4" at 61.041,65.204 h1.2 r45
  text "A2" at 7.866,64.129 h1.2 r315
  text "PWM" at 61.016,63.729 h1.2 r45
  text "D3" at 61.016,62.504 h1.2 r45
  text "A3" at 7.766,61.479 h1.2 r315
  text "USART" at 16.249,61.35 h1.5 r90
  text "I/O" at 61.016,61.129 h1.2 r45
  text "D2" at 61.041,59.954 h1.2 r45
  text "ADC_IN" at 54.018,59.134 h1.5 r90
  text "A4" at 7.816,59.004 h1.2 r315
  text "TX" at 60.992,58.483 h1.2 r45
  text "D1" at 60.991,57.254 h1.2 r45
  text "A5" at 7.766,56.429 h1.2 r315
  text "RX" at 61.016,55.729 h1.2 r45
  text "GND" at 14.885,55.395 h1.5
  text "D0" at 61.041,54.554 h1.2 r45
  text "COMP" at 8.392,50.222 h1.5 r90
  text "QSPI" at 53.866,49.124 h1.5 r90
  text "SAI_A" at 16.036,47.769 h1.5 r90
  text "I2C" at 8.534,44.676 h1.5 r90
  text "TIMER" at 62.301,41.166 h1.5 r90
  text "GND" at 7.366,41.129 h1.2 r315
  text "GND" at 52.309,40.207 h1.5
  text "SAI_B" at 16,37.601 h1.5 r90
  text "CAN" at 8.356,35.361 h1.5 r90
  text "TIMER" at 54.094,33.405 h1.5 r90
  text "IO" at 14.929,32.577 h1.5
  text "IO" at 8.202,32.51 h1.5
  text "J" at 51.175,19.45 h15
  text "MB1364E" at 51.85,18.252 h2
  text "Nucleo" at 8.393,16.043 h3.3
  text "GND" at 3.225,10.45 h1.5
  text "GND" at 64.25,10.45 h1.5
  text "USER" at 5.993,2.015 h1.5
  text "RESET" at 60.307,1.922 h1.5
  text "User" at 13.205,1.729 h1.5
  text "USB" at 13.229,0.491 h1.5
  text "OVCR" at 26.258,0.329 h1.5
  text "VBUS" at 31.537,0.337 h1.5
Bottom Overlay:
  lines w0.127: 23.525,19.75 48.525,19.75 48.525,28.75 23.525,28.75 23.525,19.75
  text "GND" at 68.45,126.875 h1.5 r270
  text "GND" at 0.625,126.775 h1.5 r270
  text "F" at 42.75,116.975 h11.5
  text "G" at 31.15,116.8 h11
  text "CN12" at 65.375,103.175 h1.5
  text "CN11" at 6.265,103.098 h1.5
  text "CN7" at 57.199,102.184 h1.5
  text "PC8" at 69.75,101.975 h1.2 r45
  text "PC11" at 9.321,101.175 h1.2
  text "PC9" at 63.084,101.175 h1.2
  text "PC10" at 2.068,99.65 h1.2 r315
  text "PC6" at 69.75,99.435 h1.2 r45
  text "PD2" at 8.865,98.635 h1.2
  text "PB8" at 63.084,98.635 h1.2
  text "PC12" at 2.065,97.635 h1.2 r315
  text "PC5" at 69.75,96.895 h1.2 r45
  text "E5V" at 8.853,96.095 h1.2
  text "PB9" at 63.084,96.095 h1.2
  text "VDD" at 1.814,95.156 h1.2 r315
  text "U5V" at 69.75,94.355 h1.2 r45
  text "VREF+" at 63.082,93.564 h1.2
  text "GND" at 9.188,93.555 h1.2
  text "CN8" at 13.547,92.934 h1.5
  text "BT0" at 1.565,92.73 h1.2 r315
  text "PD8" at 69.75,91.815 h1.2 r45
  text "NC" at 8.342,91.015 h1.2
  text "GND" at 63.084,91.015 h1.2
  text "PF6" at 1.564,90.215 h1.2 r315
  text "PA12" at 69.759,89.275 h1.2 r45
  text "IOREF" at 9.872,88.475 h1.2
  text "PA5" at 63.084,88.475 h1.2
  text "PF7" at 1.554,87.7 h1.2 r315
  text "PA11" at 69.759,86.735 h1.2 r45
  text "NRST" at 9.709,85.935 h1.2
  text "PA6" at 63.084,85.935 h1.2
  text "PA13" at 2.028,84.885 h1.2 r315
  text "PB12" at 69.759,84.195 h1.2 r45
  text "3V3" at 8.733,83.395 h1.2
  text "PA7" at 63.084,83.395 h1.2
  text "PA14" at 2.017,82.345 h1.2 r315
  text "PB11" at 69.759,81.655 h1.2 r45
  text "5V" at 8.24,80.855 h1.2
  text "PB6" at 63.084,80.855 h1.2
  text "PA15" at 2.032,79.78 h1.2 r315
  text "GND" at 69.75,79.115 h1.2 r45
  text "GND" at 9.188,78.315 h1.2
  text "PC7" at 63.084,78.315 h1.2
  text "GND" at 1.871,77.34 h1.2 r315
  text "PB2" at 69.759,76.575 h1.2 r45
  text "GND" at 9.188,75.775 h1.2
  text "PA9" at 63.084,75.775 h1.2
  text "CN10" at 59.578,75.041 h1.5
  text "PB7" at 1.597,74.95 h1.2 r315
  text "PB1" at 69.759,74.035 h1.2 r45
  text "VIN" at 8.614,73.235 h1.2
  text "PA8" at 63.084,73.235 h1.2
  text "PC13" at 2.07,72.16 h1.2 r315
  text "PB15" at 69.75,71.495 h1.2 r45
  text "NC" at 8.342,70.695 h1.2
  text "PB10" at 63.084,70.695 h1.2
  text "CN9" at 13.647,69.951 h1.5
  text "PC14" at 2.068,69.595 h1.2 r315
  text "PB14" at 69.759,68.955 h1.2 r45
  text "PA0" at 8.812,68.155 h1.2
  text "PB4" at 63.084,68.155 h1.2
  text "PC15" at 2.074,67.055 h1.2 r315
  text "PB13" at 69.75,66.415 h1.2 r45
  text "PA1" at 8.665,65.615 h1.2
  text "PB5" at 63.084,65.615 h1.2
  text "OSCI" at 2.015,64.54 h1.2 r315
  text "AGND" at 69.75,63.875 h1.2 r45
  text "PA4" at 8.811,63.075 h1.2
  text "PB3" at 63.084,63.075 h1.2
  text "OSCO" at 2.429,61.7 h1.2 r315
  text "PC4" at 69.75,61.335 h1.2 r45
  text "PB0" at 8.812,60.535 h1.2
  text "PA10" at 63.084,60.535 h1.2
  text "VBAT" at 2.219,59.26 h1.2 r315
  text "PF5" at 69.75,58.795 h1.2 r45
  text "PC1" at 8.724,57.995 h1.2
  text "PA2" at 63.084,57.995 h1.2
  text "PC2" at 1.642,57.12 h1.2 r315
  text "PF4" at 69.759,56.255 h1.2 r45
  text "PC0" at 8.871,55.455 h1.2
  text "PA3" at 63.084,55.455 h1.2
  text "PC3" at 1.648,54.605 h1.2 r315
  text "PE8" at 69.75,53.715 h1.2 r45
  text "PD3" at 8.873,52.915 h1.2
  text "GND" at 63.084,52.915 h1.2
  text "PD4" at 1.636,52.09 h1.2 r315
  text "PF10" at 69.75,51.175 h1.2 r45
  text "PG2" at 8.925,50.375 h1.2
  text "PD13" at 63.084,50.375 h1.2
  text "PD5" at 1.652,49.5 h1.2 r315
  text "PE7" at 69.759,48.635 h1.2 r45
  text "PG3" at 8.933,47.835 h1.2
  text "PD12" at 63.084,47.835 h1.2
  text "PD6" at 1.648,47.01 h1.2 r315
  text "PD14" at 69.759,46.095 h1.2 r45
  text "PE2" at 8.806,45.295 h1.2
  text "PD11" at 63.084,45.295 h1.2
  text "PD7" at 1.638,44.47 h1.2 r315
  text "PD15" at 69.75,43.555 h1.2 r45
  text "PE4" at 8.811,42.755 h1.2
  text "PE10" at 63.084,42.755 h1.2
  text "PE3" at 1.606,41.93 h1.2 r315
  text "PF14" at 69.759,41.015 h1.2 r45
  text "PE5" at 8.819,40.215 h1.2
  text "PE12" at 63.084,40.215 h1.2
  text "GND" at 1.871,39.215 h1.2 r315
  text "PE9" at 69.75,38.475 h1.2 r45
  text "PF2" at 8.746,37.675 h1.2
  text "PE14" at 63.084,37.675 h1.2
  text "PF1" at 1.449,36.925 h1.2 r315
  text "GND" at 69.75,35.935 h1.2 r45
  text "PF8" at 8.755,35.135 h1.2
  text "PE15" at 63.084,35.135 h1.2
  text "PF0" at 1.562,34.385 h1.2 r315
  text "PE11" at 69.759,33.395 h1.2 r45
  text "PF9" at 8.755,32.595 h1.2
  text "PE13" at 63.084,32.595 h1.2
  text "PD1" at 1.533,31.845 h1.2 r315
  text "PF3" at 69.75,30.855 h1.2 r45
  text "PG1" at 8.784,30.055 h1.2
  text "PF13" at 63.084,30.055 h1.2
  text "J" at 34,29.35 h15
  text "PD0" at 1.646,29.305 h1.2 r315
  text "PF15" at 69.75,28.315 h1.2 r45
  text "GND" at 9.188,27.515 h1.2
  text "PF12" at 63.084,27.515 h1.2
  text "PG0" at 1.689,26.765 h1.2 r315
  text "PF11" at 69.759,25.775 h1.2 r45
  text "PE6" at 8.814,24.975 h1.2
  text "PG14" at 63.084,24.975 h1.2
  text "PE1" at 1.492,24.225 h1.2 r315
  text "PE0" at 69.75,23.235 h1.2 r45
  text "PG15" at 9.535,22.435 h1.2
  text "GND" at 63.084,22.435 h1.2
  text "PG9" at 1.691,21.685 h1.2 r315
  text "PG8" at 69.75,20.695 h1.2 r45
  text "H" at 22.325,20.025 h17.5
  text "PG10" at 9.528,19.895 h1.2
  text "PD10" at 63.084,19.895 h1.2
  text "PG12" at 2.107,18.745 h1.2 r315
  text "PG5" at 69.75,18.155 h1.2 r45
  text "PG13" at 9.53,17.355 h1.2
  text "PG7" at 63.084,17.355 h1.2
  text "MB1364E" at 41.475,17.25 h2.5
  text "NC" at 1.273,16.73 h1.2 r315
  text "PG6" at 69.75,15.615 h1.2 r45
  text "PG11" at 9.381,14.815 h1.2
  text "PG4" at 63.084,14.815 h1.2
  text "PD9" at 1.649,14.215 h1.2 r315
  text "GND" at 5.975,10.075 h1.5
  text "GND" at 67,10.075 h1.5
  text "I" at 13.45,3.35 h8
  text "C" at 8.45,3.125 h9
Top Solder:
  region: 67.75,103.85 67.75,112.35 65.75,112.35 65.75,103.85
Bottom Solder:
  region: 67.75,103.85 67.75,112.35 65.75,112.35 65.75,103.85
M1-Board Shape:
  lines w0.1: 51.369,6.4 ccw(c51.369,7.3) 52.269,7.3 ; 51.369,6.4 ccw(c51.369,6.4) 51.369,6.4 ; 51.369,6.4 51.369,0 68,0 ; 52.269,7.3 ccw(c51.369,7.3) 51.369,8.2 37.369,8.2 ccw(c37.369,7.3) 36.469,7.3 ccw(c37.369,7.3) 37.369,6.4 37.369,0 2,0 cw(c2,2) 0,2 0,131.34 cw(c2,131.34) 2,133.34 68,133.34 cw(c68,131.34) 70,131.34 70,2 cw(c68,2) 68,0 ; 52.269,7.3 52.269,7.3 ; 68,0 68,0
M5-Top Constraints:
  lines w0.2: 78.489,0.753 78.489,14.268 ; 78.489,4.268 167.989,4.268 ; 78.489,7.768 167.989,7.768 ; 78.489,20.565 78.489,34.08 ; 78.489,24.08 167.989,24.08 ; 78.489,27.58 167.989,27.58 ; 78.489,40.504 78.489,54.019 ; 78.489,44.019 167.989,44.019 ; 78.489,47.519 167.989,47.519 ; 78.494,0.753 167.994,0.753 ; 78.494,4.253 167.994,4.253 ; 78.494,20.565 167.994,20.565 ; 78.494,24.065 167.994,24.065 ; 78.494,40.504 167.994,40.504 ; 78.494,44.004 167.994,44.004 ; 79.239,16.018 104.239,16.018 ; 79.239,35.83 104.239,35.83 ; 79.239,55.769 104.239,55.769 ; 98.989,0.753 98.989,14.268 ; 98.989,20.565 98.989,34.08 ; 98.989,40.504 98.989,54.019 ; 109.489,0.753 109.489,14.268 ; 109.489,20.565 109.489,34.08 ; 109.489,40.504 109.489,54.019 ; 122.989,0.753 122.989,14.268 ; 122.989,20.565 122.989,34.08 ; 122.989,40.504 122.989,54.019 ; 139.989,0.753 139.989,14.268 ; 139.989,20.565 139.989,34.08 ; 139.989,40.504 139.989,54.019 ; 156.989,0.753 156.989,14.268 ; 156.989,20.565 156.989,34.08 ; 156.989,40.504 156.989,54.019 ; 167.989,0.753 167.989,14.268 ; 167.989,20.565 167.989,34.08 ; 167.989,40.504 167.989,54.019 ; 78.489,14.268 98.989,14.268 ; 78.489,14.268 78.489,19.518 167.989,19.518 167.989,14.268 ; 78.489,14.268 78.489,14.268 ; 78.489,34.08 98.989,34.08 ; 78.489,34.08 78.489,39.33 167.989,39.33 167.989,34.08 ; 78.489,34.08 78.489,34.08 ; 78.489,54.019 78.489,54.019 ; 78.489,54.019 78.489,59.269 167.989,59.269 167.989,54.019 ; 78.489,54.019 98.989,54.019 ; 98.989,14.268 109.489,14.268 ; 98.989,34.08 109.489,34.08 ; 98.989,54.019 109.489,54.019 ; 109.489,14.268 122.989,14.268 ; 109.489,34.08 122.989,34.08 ; 109.489,54.019 122.989,54.019 ; 122.989,14.268 139.989,14.268 ; 122.989,34.08 139.989,34.08 ; 122.989,54.019 139.989,54.019 ; 139.989,14.268 156.989,14.268 ; 139.989,34.08 156.989,34.08 ; 139.989,54.019 156.989,54.019 ; 156.989,14.268 167.989,14.268 ; 156.989,34.08 167.989,34.08 ; 156.989,54.019 167.989,54.019
  text "IMPEDANCE TABLE    RMII" at 79.239,56.269 h3
  text "LAYER" at 83.489,51.269 h3
  text "TRACE" at 99.739,51.269 h3
  text "SPACING" at 110.239,51.269 h3
  text "IMPEDANCE" at 123.739,51.269 h3
  text "IMPEDANCE" at 140.739,51.269 h3
  text "TOL." at 159.489,51.269 h3
  text "(mm)" at 113.564,48.794 h2.5
  text "(mm)" at 101.739,48.744 h2.5
  text "(Single ended)" at 124.239,48.519 h2.5
  text "(Differential)" at 141.989,48.519 h2.5
  text "+/- 15%" at 158.544,44.879 h3
  text "0.127" at 100.714,44.794 h3
  text "n/a" at 112.739,44.769 h3
  text "TOP/BOTTOM" at 79.719,44.754 h3
  text "50 ohm" at 127.094,44.704 h3
  text "n/a" at 146.644,44.654 h3
  text "+/- 15%" at 158.549,41.364 h3
  text "0.102" at 100.719,41.279 h3
  text "n/a" at 112.744,41.254 h3
  text "LAYER 3" at 81.664,41.219 h3
  text "50 ohm" at 127.099,41.189 h3
  text "n/a" at 146.649,41.139 h3
  text "IMPEDANCE TABLE    RD / RX / TD / TX" at 79.239,35.949 h3
  text "LAYER" at 83.489,31.33 h3
  text "TRACE" at 99.739,31.33 h3
  text "SPACING" at 110.239,31.33 h3
  text "IMPEDANCE" at 123.739,31.33 h3
  text "IMPEDANCE" at 140.739,31.33 h3
  text "TOL." at 159.489,31.33 h3
  text "(mm)" at 113.564,28.855 h2.5
  text "(mm)" at 101.739,28.805 h2.5
  text "(Single ended)" at 124.239,28.58 h2.5
  text "(Differential)" at 141.989,28.58 h2.5
  text "+/- 15%" at 158.544,24.94 h3
  text "0.130" at 100.714,24.855 h3
  text "0.251" at 112.739,24.83 h3
  text "TOP/BOTTOM" at 79.719,24.815 h3
  text "n/a" at 127.094,24.765 h3
  text "100 ohm" at 143.18,24.716 h3
  text "+/- 15%" at 158.549,21.425 h3
  text "0.104" at 100.719,21.34 h3
  text "0.277" at 112.744,21.315 h3
  text "LAYER 3" at 81.664,21.28 h3
  text "100 ohm" at 143.18,21.287 h3
  text "n/a" at 127.099,21.25 h3
  text "IMPEDANCE TABLE   USB FS, USB HS USER, USB HS STLINK" at 79.239,16.518 h3
  text "LAYER" at 83.489,11.518 h3
  text "TRACE" at 99.739,11.518 h3
  text "SPACING" at 110.239,11.518 h3
  text "IMPEDANCE" at 123.739,11.518 h3
  text "IMPEDANCE" at 140.739,11.518 h3
  text "TOL." at 159.489,11.518 h3
  text "(mm)" at 113.564,9.043 h2.5
  text "(mm)" at 101.739,8.993 h2.5
  text "(Single ended)" at 124.239,8.768 h2.5
  text "(Differential)" at 141.989,8.768 h2.5
  text "+/- 15%" at 158.544,5.128 h3
  text "0.155" at 100.714,5.043 h3
  text "0.226" at 112.739,5.018 h3
  text "TOP/BOTTOM" at 79.719,5.003 h3
  text "n/a" at 127.094,4.953 h3
  text "90 ohm" at 143.18,4.777 h3
  text "+/- 15%" at 158.549,1.613 h3
  text "0.130" at 100.719,1.528 h3
  text "0.251" at 112.744,1.503 h3
  text "LAYER 3" at 81.664,1.468 h3
  text "90 ohm" at 143.18,1.475 h3
  text "n/a" at 127.099,1.438 h3
Drill Drawing:
  drawing of 495 lines, arcs and shapes, not listed
  text "THE COMPONENTS WITH PLATED THROUGH HOLE (PTH) MAY BE WELDED (CABLED) IN \"PIN-IN-PASTE\" MODE (IF NECESSARY)" at 1.025,183.45 h3.5
  text "PCB SPECIFICATIONS :" at 2.061,176.279 h3
  text "PCB : TYPE 3" at 150.473,176.047 h3
  text "A.   MATERIAL :" at 2.061,172.279 h3
  text "FR-4" at 40.561,172.279 h3
  text "TG-170" at 57.061,172.279 h3
  text "X  TG-150" at 75.311,172.279 h3
  text "TG-140" at 91.311,172.279 h3
  text "ASPECT-RATIO, AXE Z :" at 150.473,170.547 h3
  text "B.   MATERIAL FAMILY :" at 2.061,169.279 h3
  text "N/A" at 40.561,169.279 h3
  text "C.   SOLDERMASK COLOR :" at 2.061,166.279 h3
  text "GREEN" at 40.561,166.279 h3
  text "X  WHITE" at 57.061,166.279 h3
  text "RED" at 75.311,166.279 h3
  text "BLACK" at 91.311,166.279 h3
  text "6:1 to 8:1 / LEVEL \"B\"" at 150.491,163.799 h3
  text "D.   SILKSCREEN COLOR :" at 2.061,163.279 h3
  text "WHITE" at 40.561,163.279 h3
  text "YELLOW" at 57.061,163.279 h3
  text "BLACK" at 75.311,163.279 h3
  text "X  Blue ink PANTONE 2955" at 91.311,163.279 h3
  text "E.   SURFACE FINISH :" at 2.061,160.279 h3
  text "X  ENIG" at 40.561,160.279 h3
  text "IMMERSION SILVER" at 57.061,160.279 h3
  text "IMMERSION TIN" at 91.311,160.279 h3
  text "MINIMUM PARAMETERS" at 150.518,158.198 h3
  text "HASL" at 40.561,157.279 h3
  text "HASL (PB-FREE)" at 57.061,157.279 h3
  text "GOLDEN FINGER" at 91.311,157.279 h3
  text "F.   IMPEDANCE CONTROL :" at 2.061,154.279 h3
  text "NO" at 40.561,154.279 h3
  text "X  YES  (SEE IMPEDANCE TABLE FOR DETAIL INFORMATION)" at 57.061,154.279 h3
  text "DEFAULT" at 150.518,152.698 h3
  text "G.   THROUGH VIA :" at 2.061,151.279 h3
  text "PLUG THE VIAS WHICH ARE COVERED WITH SOLDERMASK ONE OR TWO SIDE." at 40.561,151.279 h3
  text "PLUG MATERIAL :" at 40.561,148.279 h3
  text "X  SOLDERMASK" at 66.061,148.279 h3
  text "NON-CONDUCTIVE EPOXY." at 91.311,148.279 h3
  text "TRACKS : 0.120mm           / GAPS : 0.120mm" at 150.518,146.948 h3
  text "H.   STACK-UP :" at 2.061,145.279 h3
  text "SEE LAYER STACK-UP SEQUENCE FOR OVERALL THICKNESS." at 40.561,145.279 h3
  text "Layer" at 79.741,134.779 h2
  text "Name" at 88.115,134.779 h2
  text "Material" at 104.312,134.779 h2
  text "Thickness" at 118.866,134.779 h2
  text "Constant" at 130.821,134.779 h2
  text "Board Layer Stack" at 141.885,134.779 h2
  text "1" at 79.741,130.779 h2
  text "Top Overlay" at 88.115,130.779 h2
  text "2" at 79.741,126.779 h2
  text "Top Solder" at 88.115,126.779 h2
  text "Solder Resist" at 104.312,126.779 h2
  text "0,015mm" at 118.866,126.779 h2
  text "3,5" at 130.821,126.779 h2
  text "3" at 79.741,122.779 h2
  text "Top Layer" at 88.115,122.779 h2
  text "Copper" at 104.312,122.779 h2
  text "0,042mm" at 118.866,122.779 h2
  text "4" at 79.741,118.779 h2
  text "Dielectric 1" at 88.115,118.779 h2
  text "FR-4" at 104.312,118.779 h2
  text "0,099mm" at 118.866,118.779 h2
  text "4,2" at 130.821,118.779 h2
  text "5" at 79.741,114.779 h2
  text "Signal Layer 1" at 88.115,114.779 h2
  text "Copper" at 104.312,114.779 h2
  text "0,035mm" at 118.866,114.779 h2
  text "6" at 79.741,110.779 h2
  text "Dielectric 2" at 88.115,110.779 h2
  text "0,102mm" at 118.866,110.779 h2
  text "4,2" at 130.821,110.779 h2
  text "7" at 79.741,106.779 h2
  text "Signal Layer 2" at 88.115,106.779 h2
  text "Copper" at 104.312,106.779 h2
  text "0,035mm" at 118.866,106.779 h2
  text "8" at 79.741,102.779 h2
  text "Dielectric 3" at 88.115,102.779 h2
  text "0,946mm" at 118.866,102.779 h2
  text "4,2" at 130.821,102.779 h2
  text "9" at 79.741,98.779 h2
  text "Signal Layer 3" at 88.115,98.779 h2
  text "Copper" at 104.312,98.779 h2
  text "0,035mm" at 118.866,98.779 h2
  text "10" at 79.741,94.779 h2
  text "Dielectric 4" at 88.115,94.779 h2
  text "0,102mm" at 118.866,94.779 h2
  text "4,2" at 130.821,94.779 h2
  text "11" at 79.741,90.779 h2
  text "Signal Layer 4" at 88.115,90.779 h2
  text "Copper" at 104.312,90.779 h2
  text "0,035mm" at 118.866,90.779 h2
  text "12" at 79.741,86.779 h2
  text "Dielectric 5" at 88.115,86.779 h2
  text "0,099mm" at 118.866,86.779 h2
  text "4,2" at 130.821,86.779 h2
  text "13" at 79.741,82.779 h2
  text "Bottom Layer" at 88.115,82.779 h2
  text "Copper" at 104.312,82.779 h2
  text "0,042mm" at 118.866,82.779 h2
  text "14" at 79.741,78.779 h2
  text "Bottom Solder" at 88.115,78.779 h2
  text "Solder Resist" at 104.312,78.779 h2
  text "0,015mm" at 118.866,78.779 h2
  text "3,5" at 130.821,78.779 h2
  text "15" at 79.741,74.779 h2
  text "Bottom Overlay" at 88.115,74.779 h2
  text "Symbol" at 80.452,67.033 h2.4
  text "Count" at 89.851,67.033 h2.4
  text "Hole Size" at 100.625,67.033 h2.4
  text "Plated" at 119.896,67.033 h2.4
  text "Hole Type" at 128.147,67.033 h2.4
  text "Drill Layer Pair" at 140.158,67.033 h2.4
  text "Hole Length" at 162.939,67.033 h2.4
  text "Routed Path Length" at 181.238,67.033 h2.4
  text "2000" at 89.851,62.89 h2
  text "0,200mm (7,87mil)" at 100.625,62.89 h2
  text "PTH" at 119.896,62.89 h2
  text "Round" at 128.147,62.89 h2
  text "Top Layer - Bottom Layer" at 140.158,62.89 h2
  text "-" at 162.939,62.89 h2
  text "-" at 181.238,62.89 h2
  text "9" at 89.851,58.747 h2
  text "0,300mm (11,81mil)" at 100.625,58.747 h2
  text "PTH" at 119.896,58.747 h2
  text "Round" at 128.147,58.747 h2
  text "Top Layer - Bottom Layer" at 140.158,58.747 h2
  text "-" at 162.939,58.747 h2
  text "-" at 181.238,58.747 h2
  text "4" at 89.851,54.604 h2
  text "0,600mm (23,62mil)" at 100.625,54.604 h2
  text "PTH" at 119.896,54.604 h2
  text "Slot" at 128.147,54.604 h2
  text "Top Layer - Bottom Layer" at 140.158,54.604 h2
  text "1,300mm (51,18mil)" at 162.939,54.604 h2
  text "0,700mm (27,56mil)" at 181.238,54.604 h2
  text "2" at 89.851,50.461 h2
  text "0,650mm (25,59mil)" at 100.625,50.461 h2
  text "PTH" at 119.896,50.461 h2
  text "Slot" at 128.147,50.461 h2
  text "Top Layer - Bottom Layer" at 140.158,50.461 h2
  text "0,850mm (33,47mil)" at 162.939,50.461 h2
  text "0,200mm (7,88mil)" at 181.238,50.461 h2
  text "12" at 89.851,46.318 h2
  text "0,700mm (27,56mil)" at 100.625,46.318 h2
  text "PTH" at 119.896,46.318 h2
  text "Round" at 128.147,46.318 h2
  text "Top Layer - Bottom Layer" at 140.158,46.318 h2
  text "-" at 162.939,46.318 h2
  text "-" at 181.238,46.318 h2
  text "2" at 89.851,42.175 h2
  text "0,700mm (27,56mil)" at 100.625,42.175 h2
  text "PTH" at 119.896,42.175 h2
  text "Slot" at 128.147,42.175 h2
  text "Top Layer - Bottom Layer" at 140.158,42.175 h2
  text "2,200mm (86,61mil)" at 162.939,42.175 h2
  text "1,500mm (59,06mil)" at 181.238,42.175 h2
  text "2" at 89.851,38.032 h2
  text "0,850mm (33,47mil)" at 100.625,38.032 h2
  text "NPTH" at 119.896,38.032 h2
  text "Slot" at 128.147,38.032 h2
  text "Top Layer - Bottom Layer" at 140.158,38.032 h2
  text "2,425mm (95,47mil)" at 162.939,38.032 h2
  text "1,575mm (62,01mil)" at 181.238,38.032 h2
  text "2" at 89.851,33.889 h2
  text "0,900mm (35,43mil)" at 100.625,33.889 h2
  text "PTH" at 119.896,33.889 h2
  text "Round" at 128.147,33.889 h2
  text "Top Layer - Bottom Layer" at 140.158,33.889 h2
  text "-" at 162.939,33.889 h2
  text "-" at 181.238,33.889 h2
  text "2" at 89.851,29.746 h2
  text "0,970mm (38,19mil)" at 100.625,29.746 h2
  text "NPTH" at 119.896,29.746 h2
  text "Round" at 128.147,29.746 h2
  text "Top Layer - Bottom Layer" at 140.158,29.746 h2
  text "-" at 162.939,29.746 h2
  text "-" at 181.238,29.746 h2
  text "B" at 79.664,29.492 h1.84
  text "171" at 89.851,25.603 h2
  text "1,000mm (39,37mil)" at 100.625,25.603 h2
  text "PTH" at 119.896,25.603 h2
  text "Round" at 128.147,25.603 h2
  text "Top Layer - Bottom Layer" at 140.158,25.603 h2
  text "-" at 162.939,25.603 h2
  text "-" at 181.238,25.603 h2
  text "100" at 89.851,21.46 h2
  text "1,100mm (43,31mil)" at 100.625,21.46 h2
  text "PTH" at 119.896,21.46 h2
  text "Round" at 128.147,21.46 h2
  text "Top Layer - Bottom Layer" at 140.158,21.46 h2
  text "-" at 162.939,21.46 h2
  text "-" at 181.238,21.46 h2
  text "2" at 89.851,17.316 h2
  text "1,190mm (46,85mil)" at 100.625,17.316 h2
  text "NPTH" at 119.896,17.316 h2
  text "Round" at 128.147,17.316 h2
  text "Top Layer - Bottom Layer" at 140.158,17.316 h2
  text "-" at 162.939,17.316 h2
  text "-" at 181.238,17.316 h2
  text "C" at 79.664,17.063 h1.84
  text "2" at 89.851,13.173 h2
  text "1,500mm (59,06mil)" at 100.625,13.173 h2
  text "NPTH" at 119.896,13.173 h2
  text "Round" at 128.147,13.173 h2
  text "Top Layer - Bottom Layer" at 140.158,13.173 h2
  text "-" at 162.939,13.173 h2
  text "-" at 181.238,13.173 h2
  text "5" at 89.851,9.03 h2
  text "3,200mm (125,98mil)" at 100.625,9.03 h2
  text "NPTH" at 119.896,9.03 h2
  text "Round" at 128.147,9.03 h2
  text "Top Layer - Bottom Layer" at 140.158,9.03 h2
  text "-" at 162.939,9.03 h2
  text "-" at 181.238,9.03 h2
  text "2315 Total" at 89.851,4.887 h2
  text "Slot definitions :" at 80.452,1.987 h2
  text "Routed Path Length" at 94.105,1.987 h2
  text "= Calculated from tool start centre position to tool end centre position." at 111.018,1.987 h2
  text "Hole Length" at 94.105,0.33 h2
  text "= Routed Path Length + Tool Size = Slot length as defined in the PCB layout" at 104.739,0.33 h2

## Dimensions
2,0 to 2,133.34 on M2-Board Dimensions
0,131.34 to 70,131.34 on M2-Board Dimensions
